VERSION 5.8 ;
BUSBITCHARS "[]" ;
DIVIDERCHAR "/" ;
UNITS
    DATABASE MICRONS 1000 ;
END UNITS

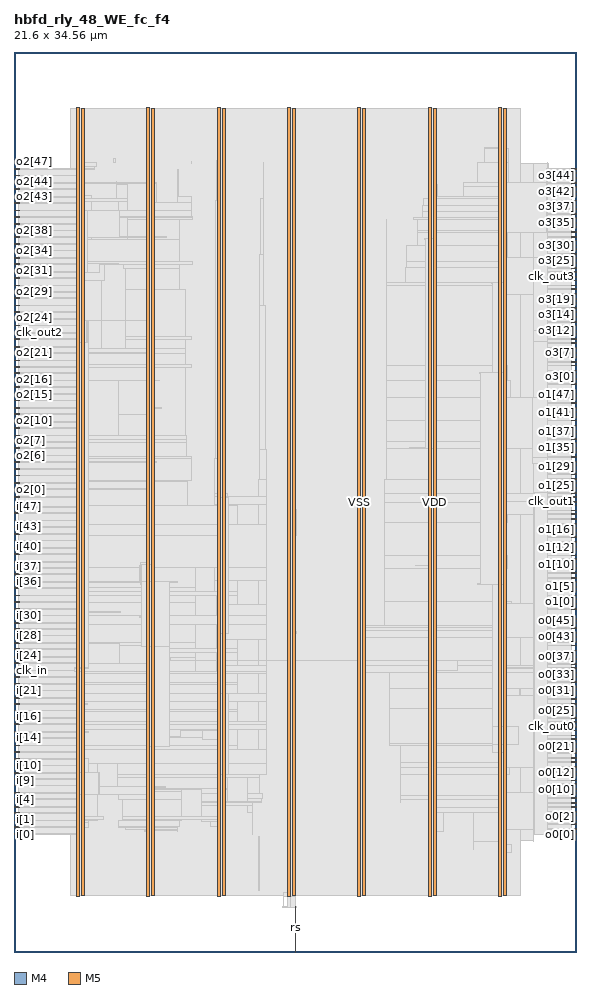
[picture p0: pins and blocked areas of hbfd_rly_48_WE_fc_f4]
MACRO hbfd_rly_48_WE_fc_f4
  FOREIGN hbfd_rly_48_WE_fc_f4 0 0 ;
  CLASS BLOCK ;
  SIZE 21.6 BY 34.56 ;
  PIN clk_in
    DIRECTION INPUT ;
    USE SIGNAL ;
    PORT
      LAYER M4 ;
        RECT  0 10.8 0.192 10.824 ;
    END
  END clk_in
  PIN clk_out0
    DIRECTION OUTPUT ;
    USE SIGNAL ;
    PORT
      LAYER M4 ;
        RECT  21.408 8.64 21.6 8.664 ;
    END
  END clk_out0
  PIN clk_out1
    DIRECTION OUTPUT ;
    USE SIGNAL ;
    PORT
      LAYER M4 ;
        RECT  21.408 17.28 21.6 17.304 ;
    END
  END clk_out1
  PIN clk_out2
    DIRECTION OUTPUT ;
    USE SIGNAL ;
    PORT
      LAYER M4 ;
        RECT  0 23.76 0.192 23.784 ;
    END
  END clk_out2
  PIN clk_out3
    DIRECTION OUTPUT ;
    USE SIGNAL ;
    PORT
      LAYER M4 ;
        RECT  21.408 25.92 21.6 25.944 ;
    END
  END clk_out3
  PIN i[0]
    DIRECTION INPUT ;
    USE SIGNAL ;
    PORT
      LAYER M4 ;
        RECT  0 4.512 0.192 4.536 ;
    END
  END i[0]
  PIN i[10]
    DIRECTION INPUT ;
    USE SIGNAL ;
    PORT
      LAYER M4 ;
        RECT  0 7.152 0.192 7.176 ;
    END
  END i[10]
  PIN i[11]
    DIRECTION INPUT ;
    USE SIGNAL ;
    PORT
      LAYER M4 ;
        RECT  0 7.392 0.192 7.416 ;
    END
  END i[11]
  PIN i[12]
    DIRECTION INPUT ;
    USE SIGNAL ;
    PORT
      LAYER M4 ;
        RECT  0 7.68 0.192 7.704 ;
    END
  END i[12]
  PIN i[13]
    DIRECTION INPUT ;
    USE SIGNAL ;
    PORT
      LAYER M4 ;
        RECT  0 7.92 0.192 7.944 ;
    END
  END i[13]
  PIN i[14]
    DIRECTION INPUT ;
    USE SIGNAL ;
    PORT
      LAYER M4 ;
        RECT  0 8.208 0.192 8.232 ;
    END
  END i[14]
  PIN i[15]
    DIRECTION INPUT ;
    USE SIGNAL ;
    PORT
      LAYER M4 ;
        RECT  0 8.448 0.192 8.472 ;
    END
  END i[15]
  PIN i[16]
    DIRECTION INPUT ;
    USE SIGNAL ;
    PORT
      LAYER M4 ;
        RECT  0 8.736 0.192 8.76 ;
    END
  END i[16]
  PIN i[17]
    DIRECTION INPUT ;
    USE SIGNAL ;
    PORT
      LAYER M4 ;
        RECT  0 8.976 0.192 9 ;
    END
  END i[17]
  PIN i[18]
    DIRECTION INPUT ;
    USE SIGNAL ;
    PORT
      LAYER M4 ;
        RECT  0 9.264 0.192 9.288 ;
    END
  END i[18]
  PIN i[19]
    DIRECTION INPUT ;
    USE SIGNAL ;
    PORT
      LAYER M4 ;
        RECT  0 9.504 0.192 9.528 ;
    END
  END i[19]
  PIN i[1]
    DIRECTION INPUT ;
    USE SIGNAL ;
    PORT
      LAYER M4 ;
        RECT  0 4.8 0.192 4.824 ;
    END
  END i[1]
  PIN i[20]
    DIRECTION INPUT ;
    USE SIGNAL ;
    PORT
      LAYER M4 ;
        RECT  0 9.744 0.192 9.768 ;
    END
  END i[20]
  PIN i[21]
    DIRECTION INPUT ;
    USE SIGNAL ;
    PORT
      LAYER M4 ;
        RECT  0 10.032 0.192 10.056 ;
    END
  END i[21]
  PIN i[22]
    DIRECTION INPUT ;
    USE SIGNAL ;
    PORT
      LAYER M4 ;
        RECT  0 10.272 0.192 10.296 ;
    END
  END i[22]
  PIN i[23]
    DIRECTION INPUT ;
    USE SIGNAL ;
    PORT
      LAYER M4 ;
        RECT  0 10.56 0.192 10.584 ;
    END
  END i[23]
  PIN i[24]
    DIRECTION INPUT ;
    USE SIGNAL ;
    PORT
      LAYER M4 ;
        RECT  0 11.088 0.192 11.112 ;
    END
  END i[24]
  PIN i[25]
    DIRECTION INPUT ;
    USE SIGNAL ;
    PORT
      LAYER M4 ;
        RECT  0 11.328 0.192 11.352 ;
    END
  END i[25]
  PIN i[26]
    DIRECTION INPUT ;
    USE SIGNAL ;
    PORT
      LAYER M4 ;
        RECT  0 11.616 0.192 11.64 ;
    END
  END i[26]
  PIN i[27]
    DIRECTION INPUT ;
    USE SIGNAL ;
    PORT
      LAYER M4 ;
        RECT  0 11.856 0.192 11.88 ;
    END
  END i[27]
  PIN i[28]
    DIRECTION INPUT ;
    USE SIGNAL ;
    PORT
      LAYER M4 ;
        RECT  0 12.144 0.192 12.168 ;
    END
  END i[28]
  PIN i[29]
    DIRECTION INPUT ;
    USE SIGNAL ;
    PORT
      LAYER M4 ;
        RECT  0 12.384 0.192 12.408 ;
    END
  END i[29]
  PIN i[2]
    DIRECTION INPUT ;
    USE SIGNAL ;
    PORT
      LAYER M4 ;
        RECT  0 5.04 0.192 5.064 ;
    END
  END i[2]
  PIN i[30]
    DIRECTION INPUT ;
    USE SIGNAL ;
    PORT
      LAYER M4 ;
        RECT  0 12.624 0.192 12.648 ;
    END
  END i[30]
  PIN i[31]
    DIRECTION INPUT ;
    USE SIGNAL ;
    PORT
      LAYER M4 ;
        RECT  0 12.912 0.192 12.936 ;
    END
  END i[31]
  PIN i[32]
    DIRECTION INPUT ;
    USE SIGNAL ;
    PORT
      LAYER M4 ;
        RECT  0 13.152 0.192 13.176 ;
    END
  END i[32]
  PIN i[33]
    DIRECTION INPUT ;
    USE SIGNAL ;
    PORT
      LAYER M4 ;
        RECT  0 13.44 0.192 13.464 ;
    END
  END i[33]
  PIN i[34]
    DIRECTION INPUT ;
    USE SIGNAL ;
    PORT
      LAYER M4 ;
        RECT  0 13.68 0.192 13.704 ;
    END
  END i[34]
  PIN i[35]
    DIRECTION INPUT ;
    USE SIGNAL ;
    PORT
      LAYER M4 ;
        RECT  0 13.968 0.192 13.992 ;
    END
  END i[35]
  PIN i[36]
    DIRECTION INPUT ;
    USE SIGNAL ;
    PORT
      LAYER M4 ;
        RECT  0 14.208 0.192 14.232 ;
    END
  END i[36]
  PIN i[37]
    DIRECTION INPUT ;
    USE SIGNAL ;
    PORT
      LAYER M4 ;
        RECT  0 14.496 0.192 14.52 ;
    END
  END i[37]
  PIN i[38]
    DIRECTION INPUT ;
    USE SIGNAL ;
    PORT
      LAYER M4 ;
        RECT  0 14.736 0.192 14.76 ;
    END
  END i[38]
  PIN i[39]
    DIRECTION INPUT ;
    USE SIGNAL ;
    PORT
      LAYER M4 ;
        RECT  0 14.976 0.192 15 ;
    END
  END i[39]
  PIN i[3]
    DIRECTION INPUT ;
    USE SIGNAL ;
    PORT
      LAYER M4 ;
        RECT  0 5.328 0.192 5.352 ;
    END
  END i[3]
  PIN i[40]
    DIRECTION INPUT ;
    USE SIGNAL ;
    PORT
      LAYER M4 ;
        RECT  0 15.264 0.192 15.288 ;
    END
  END i[40]
  PIN i[41]
    DIRECTION INPUT ;
    USE SIGNAL ;
    PORT
      LAYER M4 ;
        RECT  0 15.504 0.192 15.528 ;
    END
  END i[41]
  PIN i[42]
    DIRECTION INPUT ;
    USE SIGNAL ;
    PORT
      LAYER M4 ;
        RECT  0 15.792 0.192 15.816 ;
    END
  END i[42]
  PIN i[43]
    DIRECTION INPUT ;
    USE SIGNAL ;
    PORT
      LAYER M4 ;
        RECT  0 16.032 0.192 16.056 ;
    END
  END i[43]
  PIN i[44]
    DIRECTION INPUT ;
    USE SIGNAL ;
    PORT
      LAYER M4 ;
        RECT  0 16.32 0.192 16.344 ;
    END
  END i[44]
  PIN i[45]
    DIRECTION INPUT ;
    USE SIGNAL ;
    PORT
      LAYER M4 ;
        RECT  0 16.56 0.192 16.584 ;
    END
  END i[45]
  PIN i[46]
    DIRECTION INPUT ;
    USE SIGNAL ;
    PORT
      LAYER M4 ;
        RECT  0 16.848 0.192 16.872 ;
    END
  END i[46]
  PIN i[47]
    DIRECTION INPUT ;
    USE SIGNAL ;
    PORT
      LAYER M4 ;
        RECT  0 17.088 0.192 17.112 ;
    END
  END i[47]
  PIN i[4]
    DIRECTION INPUT ;
    USE SIGNAL ;
    PORT
      LAYER M4 ;
        RECT  0 5.568 0.192 5.592 ;
    END
  END i[4]
  PIN i[5]
    DIRECTION INPUT ;
    USE SIGNAL ;
    PORT
      LAYER M4 ;
        RECT  0 5.856 0.192 5.88 ;
    END
  END i[5]
  PIN i[6]
    DIRECTION INPUT ;
    USE SIGNAL ;
    PORT
      LAYER M4 ;
        RECT  0 6.096 0.192 6.12 ;
    END
  END i[6]
  PIN i[7]
    DIRECTION INPUT ;
    USE SIGNAL ;
    PORT
      LAYER M4 ;
        RECT  0 6.384 0.192 6.408 ;
    END
  END i[7]
  PIN i[8]
    DIRECTION INPUT ;
    USE SIGNAL ;
    PORT
      LAYER M4 ;
        RECT  0 6.624 0.192 6.648 ;
    END
  END i[8]
  PIN i[9]
    DIRECTION INPUT ;
    USE SIGNAL ;
    PORT
      LAYER M4 ;
        RECT  0 6.864 0.192 6.888 ;
    END
  END i[9]
  PIN o0[0]
    DIRECTION OUTPUT ;
    USE SIGNAL ;
    PORT
      LAYER M4 ;
        RECT  21.408 4.512 21.6 4.536 ;
    END
  END o0[0]
  PIN o0[10]
    DIRECTION OUTPUT ;
    USE SIGNAL ;
    PORT
      LAYER M4 ;
        RECT  21.408 6.24 21.6 6.264 ;
    END
  END o0[10]
  PIN o0[11]
    DIRECTION OUTPUT ;
    USE SIGNAL ;
    PORT
      LAYER M4 ;
        RECT  21.408 6.432 21.6 6.456 ;
    END
  END o0[11]
  PIN o0[12]
    DIRECTION OUTPUT ;
    USE SIGNAL ;
    PORT
      LAYER M4 ;
        RECT  21.408 6.576 21.6 6.6 ;
    END
  END o0[12]
  PIN o0[13]
    DIRECTION OUTPUT ;
    USE SIGNAL ;
    PORT
      LAYER M4 ;
        RECT  21.408 6.768 21.6 6.792 ;
    END
  END o0[13]
  PIN o0[14]
    DIRECTION OUTPUT ;
    USE SIGNAL ;
    PORT
      LAYER M4 ;
        RECT  21.408 6.912 21.6 6.936 ;
    END
  END o0[14]
  PIN o0[15]
    DIRECTION OUTPUT ;
    USE SIGNAL ;
    PORT
      LAYER M4 ;
        RECT  21.408 7.104 21.6 7.128 ;
    END
  END o0[15]
  PIN o0[16]
    DIRECTION OUTPUT ;
    USE SIGNAL ;
    PORT
      LAYER M4 ;
        RECT  21.408 7.296 21.6 7.32 ;
    END
  END o0[16]
  PIN o0[17]
    DIRECTION OUTPUT ;
    USE SIGNAL ;
    PORT
      LAYER M4 ;
        RECT  21.408 7.44 21.6 7.464 ;
    END
  END o0[17]
  PIN o0[18]
    DIRECTION OUTPUT ;
    USE SIGNAL ;
    PORT
      LAYER M4 ;
        RECT  21.408 7.632 21.6 7.656 ;
    END
  END o0[18]
  PIN o0[19]
    DIRECTION OUTPUT ;
    USE SIGNAL ;
    PORT
      LAYER M4 ;
        RECT  21.408 7.776 21.6 7.8 ;
    END
  END o0[19]
  PIN o0[1]
    DIRECTION OUTPUT ;
    USE SIGNAL ;
    PORT
      LAYER M4 ;
        RECT  21.408 4.704 21.6 4.728 ;
    END
  END o0[1]
  PIN o0[20]
    DIRECTION OUTPUT ;
    USE SIGNAL ;
    PORT
      LAYER M4 ;
        RECT  21.408 7.968 21.6 7.992 ;
    END
  END o0[20]
  PIN o0[21]
    DIRECTION OUTPUT ;
    USE SIGNAL ;
    PORT
      LAYER M4 ;
        RECT  21.408 8.16 21.6 8.184 ;
    END
  END o0[21]
  PIN o0[22]
    DIRECTION OUTPUT ;
    USE SIGNAL ;
    PORT
      LAYER M4 ;
        RECT  21.408 8.304 21.6 8.328 ;
    END
  END o0[22]
  PIN o0[23]
    DIRECTION OUTPUT ;
    USE SIGNAL ;
    PORT
      LAYER M4 ;
        RECT  21.408 8.496 21.6 8.52 ;
    END
  END o0[23]
  PIN o0[24]
    DIRECTION OUTPUT ;
    USE SIGNAL ;
    PORT
      LAYER M4 ;
        RECT  21.408 8.832 21.6 8.856 ;
    END
  END o0[24]
  PIN o0[25]
    DIRECTION OUTPUT ;
    USE SIGNAL ;
    PORT
      LAYER M4 ;
        RECT  21.408 8.976 21.6 9 ;
    END
  END o0[25]
  PIN o0[26]
    DIRECTION OUTPUT ;
    USE SIGNAL ;
    PORT
      LAYER M4 ;
        RECT  21.408 9.168 21.6 9.192 ;
    END
  END o0[26]
  PIN o0[27]
    DIRECTION OUTPUT ;
    USE SIGNAL ;
    PORT
      LAYER M4 ;
        RECT  21.408 9.36 21.6 9.384 ;
    END
  END o0[27]
  PIN o0[28]
    DIRECTION OUTPUT ;
    USE SIGNAL ;
    PORT
      LAYER M4 ;
        RECT  21.408 9.504 21.6 9.528 ;
    END
  END o0[28]
  PIN o0[29]
    DIRECTION OUTPUT ;
    USE SIGNAL ;
    PORT
      LAYER M4 ;
        RECT  21.408 9.696 21.6 9.72 ;
    END
  END o0[29]
  PIN o0[2]
    DIRECTION OUTPUT ;
    USE SIGNAL ;
    PORT
      LAYER M4 ;
        RECT  21.408 4.896 21.6 4.92 ;
    END
  END o0[2]
  PIN o0[30]
    DIRECTION OUTPUT ;
    USE SIGNAL ;
    PORT
      LAYER M4 ;
        RECT  21.408 9.84 21.6 9.864 ;
    END
  END o0[30]
  PIN o0[31]
    DIRECTION OUTPUT ;
    USE SIGNAL ;
    PORT
      LAYER M4 ;
        RECT  21.408 10.032 21.6 10.056 ;
    END
  END o0[31]
  PIN o0[32]
    DIRECTION OUTPUT ;
    USE SIGNAL ;
    PORT
      LAYER M4 ;
        RECT  21.408 10.176 21.6 10.2 ;
    END
  END o0[32]
  PIN o0[33]
    DIRECTION OUTPUT ;
    USE SIGNAL ;
    PORT
      LAYER M4 ;
        RECT  21.408 10.368 21.6 10.392 ;
    END
  END o0[33]
  PIN o0[34]
    DIRECTION OUTPUT ;
    USE SIGNAL ;
    PORT
      LAYER M4 ;
        RECT  21.408 10.56 21.6 10.584 ;
    END
  END o0[34]
  PIN o0[35]
    DIRECTION OUTPUT ;
    USE SIGNAL ;
    PORT
      LAYER M4 ;
        RECT  21.408 10.704 21.6 10.728 ;
    END
  END o0[35]
  PIN o0[36]
    DIRECTION OUTPUT ;
    USE SIGNAL ;
    PORT
      LAYER M4 ;
        RECT  21.408 10.896 21.6 10.92 ;
    END
  END o0[36]
  PIN o0[37]
    DIRECTION OUTPUT ;
    USE SIGNAL ;
    PORT
      LAYER M4 ;
        RECT  21.408 11.04 21.6 11.064 ;
    END
  END o0[37]
  PIN o0[38]
    DIRECTION OUTPUT ;
    USE SIGNAL ;
    PORT
      LAYER M4 ;
        RECT  21.408 11.232 21.6 11.256 ;
    END
  END o0[38]
  PIN o0[39]
    DIRECTION OUTPUT ;
    USE SIGNAL ;
    PORT
      LAYER M4 ;
        RECT  21.408 11.376 21.6 11.4 ;
    END
  END o0[39]
  PIN o0[3]
    DIRECTION OUTPUT ;
    USE SIGNAL ;
    PORT
      LAYER M4 ;
        RECT  21.408 5.04 21.6 5.064 ;
    END
  END o0[3]
  PIN o0[40]
    DIRECTION OUTPUT ;
    USE SIGNAL ;
    PORT
      LAYER M4 ;
        RECT  21.408 11.568 21.6 11.592 ;
    END
  END o0[40]
  PIN o0[41]
    DIRECTION OUTPUT ;
    USE SIGNAL ;
    PORT
      LAYER M4 ;
        RECT  21.408 11.76 21.6 11.784 ;
    END
  END o0[41]
  PIN o0[42]
    DIRECTION OUTPUT ;
    USE SIGNAL ;
    PORT
      LAYER M4 ;
        RECT  21.408 11.904 21.6 11.928 ;
    END
  END o0[42]
  PIN o0[43]
    DIRECTION OUTPUT ;
    USE SIGNAL ;
    PORT
      LAYER M4 ;
        RECT  21.408 12.096 21.6 12.12 ;
    END
  END o0[43]
  PIN o0[44]
    DIRECTION OUTPUT ;
    USE SIGNAL ;
    PORT
      LAYER M4 ;
        RECT  21.408 12.24 21.6 12.264 ;
    END
  END o0[44]
  PIN o0[45]
    DIRECTION OUTPUT ;
    USE SIGNAL ;
    PORT
      LAYER M4 ;
        RECT  21.408 12.432 21.6 12.456 ;
    END
  END o0[45]
  PIN o0[46]
    DIRECTION OUTPUT ;
    USE SIGNAL ;
    PORT
      LAYER M4 ;
        RECT  21.408 12.624 21.6 12.648 ;
    END
  END o0[46]
  PIN o0[47]
    DIRECTION OUTPUT ;
    USE SIGNAL ;
    PORT
      LAYER M4 ;
        RECT  21.408 12.768 21.6 12.792 ;
    END
  END o0[47]
  PIN o0[4]
    DIRECTION OUTPUT ;
    USE SIGNAL ;
    PORT
      LAYER M4 ;
        RECT  21.408 5.232 21.6 5.256 ;
    END
  END o0[4]
  PIN o0[5]
    DIRECTION OUTPUT ;
    USE SIGNAL ;
    PORT
      LAYER M4 ;
        RECT  21.408 5.376 21.6 5.4 ;
    END
  END o0[5]
  PIN o0[6]
    DIRECTION OUTPUT ;
    USE SIGNAL ;
    PORT
      LAYER M4 ;
        RECT  21.408 5.568 21.6 5.592 ;
    END
  END o0[6]
  PIN o0[7]
    DIRECTION OUTPUT ;
    USE SIGNAL ;
    PORT
      LAYER M4 ;
        RECT  21.408 5.712 21.6 5.736 ;
    END
  END o0[7]
  PIN o0[8]
    DIRECTION OUTPUT ;
    USE SIGNAL ;
    PORT
      LAYER M4 ;
        RECT  21.408 5.904 21.6 5.928 ;
    END
  END o0[8]
  PIN o0[9]
    DIRECTION OUTPUT ;
    USE SIGNAL ;
    PORT
      LAYER M4 ;
        RECT  21.408 6.096 21.6 6.12 ;
    END
  END o0[9]
  PIN o1[0]
    DIRECTION OUTPUT ;
    USE SIGNAL ;
    PORT
      LAYER M4 ;
        RECT  21.408 13.152 21.6 13.176 ;
    END
  END o1[0]
  PIN o1[10]
    DIRECTION OUTPUT ;
    USE SIGNAL ;
    PORT
      LAYER M4 ;
        RECT  21.408 14.88 21.6 14.904 ;
    END
  END o1[10]
  PIN o1[11]
    DIRECTION OUTPUT ;
    USE SIGNAL ;
    PORT
      LAYER M4 ;
        RECT  21.408 15.072 21.6 15.096 ;
    END
  END o1[11]
  PIN o1[12]
    DIRECTION OUTPUT ;
    USE SIGNAL ;
    PORT
      LAYER M4 ;
        RECT  21.408 15.216 21.6 15.24 ;
    END
  END o1[12]
  PIN o1[13]
    DIRECTION OUTPUT ;
    USE SIGNAL ;
    PORT
      LAYER M4 ;
        RECT  21.408 15.408 21.6 15.432 ;
    END
  END o1[13]
  PIN o1[14]
    DIRECTION OUTPUT ;
    USE SIGNAL ;
    PORT
      LAYER M4 ;
        RECT  21.408 15.552 21.6 15.576 ;
    END
  END o1[14]
  PIN o1[15]
    DIRECTION OUTPUT ;
    USE SIGNAL ;
    PORT
      LAYER M4 ;
        RECT  21.408 15.744 21.6 15.768 ;
    END
  END o1[15]
  PIN o1[16]
    DIRECTION OUTPUT ;
    USE SIGNAL ;
    PORT
      LAYER M4 ;
        RECT  21.408 15.936 21.6 15.96 ;
    END
  END o1[16]
  PIN o1[17]
    DIRECTION OUTPUT ;
    USE SIGNAL ;
    PORT
      LAYER M4 ;
        RECT  21.408 16.08 21.6 16.104 ;
    END
  END o1[17]
  PIN o1[18]
    DIRECTION OUTPUT ;
    USE SIGNAL ;
    PORT
      LAYER M4 ;
        RECT  21.408 16.272 21.6 16.296 ;
    END
  END o1[18]
  PIN o1[19]
    DIRECTION OUTPUT ;
    USE SIGNAL ;
    PORT
      LAYER M4 ;
        RECT  21.408 16.416 21.6 16.44 ;
    END
  END o1[19]
  PIN o1[1]
    DIRECTION OUTPUT ;
    USE SIGNAL ;
    PORT
      LAYER M4 ;
        RECT  21.408 13.344 21.6 13.368 ;
    END
  END o1[1]
  PIN o1[20]
    DIRECTION OUTPUT ;
    USE SIGNAL ;
    PORT
      LAYER M4 ;
        RECT  21.408 16.608 21.6 16.632 ;
    END
  END o1[20]
  PIN o1[21]
    DIRECTION OUTPUT ;
    USE SIGNAL ;
    PORT
      LAYER M4 ;
        RECT  21.408 16.8 21.6 16.824 ;
    END
  END o1[21]
  PIN o1[22]
    DIRECTION OUTPUT ;
    USE SIGNAL ;
    PORT
      LAYER M4 ;
        RECT  21.408 16.944 21.6 16.968 ;
    END
  END o1[22]
  PIN o1[23]
    DIRECTION OUTPUT ;
    USE SIGNAL ;
    PORT
      LAYER M4 ;
        RECT  21.408 17.136 21.6 17.16 ;
    END
  END o1[23]
  PIN o1[24]
    DIRECTION OUTPUT ;
    USE SIGNAL ;
    PORT
      LAYER M4 ;
        RECT  21.408 17.472 21.6 17.496 ;
    END
  END o1[24]
  PIN o1[25]
    DIRECTION OUTPUT ;
    USE SIGNAL ;
    PORT
      LAYER M4 ;
        RECT  21.408 17.616 21.6 17.64 ;
    END
  END o1[25]
  PIN o1[26]
    DIRECTION OUTPUT ;
    USE SIGNAL ;
    PORT
      LAYER M4 ;
        RECT  21.408 17.808 21.6 17.832 ;
    END
  END o1[26]
  PIN o1[27]
    DIRECTION OUTPUT ;
    USE SIGNAL ;
    PORT
      LAYER M4 ;
        RECT  21.408 18 21.6 18.024 ;
    END
  END o1[27]
  PIN o1[28]
    DIRECTION OUTPUT ;
    USE SIGNAL ;
    PORT
      LAYER M4 ;
        RECT  21.408 18.144 21.6 18.168 ;
    END
  END o1[28]
  PIN o1[29]
    DIRECTION OUTPUT ;
    USE SIGNAL ;
    PORT
      LAYER M4 ;
        RECT  21.408 18.336 21.6 18.36 ;
    END
  END o1[29]
  PIN o1[2]
    DIRECTION OUTPUT ;
    USE SIGNAL ;
    PORT
      LAYER M4 ;
        RECT  21.408 13.536 21.6 13.56 ;
    END
  END o1[2]
  PIN o1[30]
    DIRECTION OUTPUT ;
    USE SIGNAL ;
    PORT
      LAYER M4 ;
        RECT  21.408 18.48 21.6 18.504 ;
    END
  END o1[30]
  PIN o1[31]
    DIRECTION OUTPUT ;
    USE SIGNAL ;
    PORT
      LAYER M4 ;
        RECT  21.408 18.672 21.6 18.696 ;
    END
  END o1[31]
  PIN o1[32]
    DIRECTION OUTPUT ;
    USE SIGNAL ;
    PORT
      LAYER M4 ;
        RECT  21.408 18.816 21.6 18.84 ;
    END
  END o1[32]
  PIN o1[33]
    DIRECTION OUTPUT ;
    USE SIGNAL ;
    PORT
      LAYER M4 ;
        RECT  21.408 19.008 21.6 19.032 ;
    END
  END o1[33]
  PIN o1[34]
    DIRECTION OUTPUT ;
    USE SIGNAL ;
    PORT
      LAYER M4 ;
        RECT  21.408 19.2 21.6 19.224 ;
    END
  END o1[34]
  PIN o1[35]
    DIRECTION OUTPUT ;
    USE SIGNAL ;
    PORT
      LAYER M4 ;
        RECT  21.408 19.344 21.6 19.368 ;
    END
  END o1[35]
  PIN o1[36]
    DIRECTION OUTPUT ;
    USE SIGNAL ;
    PORT
      LAYER M4 ;
        RECT  21.408 19.536 21.6 19.56 ;
    END
  END o1[36]
  PIN o1[37]
    DIRECTION OUTPUT ;
    USE SIGNAL ;
    PORT
      LAYER M4 ;
        RECT  21.408 19.68 21.6 19.704 ;
    END
  END o1[37]
  PIN o1[38]
    DIRECTION OUTPUT ;
    USE SIGNAL ;
    PORT
      LAYER M4 ;
        RECT  21.408 19.872 21.6 19.896 ;
    END
  END o1[38]
  PIN o1[39]
    DIRECTION OUTPUT ;
    USE SIGNAL ;
    PORT
      LAYER M4 ;
        RECT  21.408 20.016 21.6 20.04 ;
    END
  END o1[39]
  PIN o1[3]
    DIRECTION OUTPUT ;
    USE SIGNAL ;
    PORT
      LAYER M4 ;
        RECT  21.408 13.68 21.6 13.704 ;
    END
  END o1[3]
  PIN o1[40]
    DIRECTION OUTPUT ;
    USE SIGNAL ;
    PORT
      LAYER M4 ;
        RECT  21.408 20.208 21.6 20.232 ;
    END
  END o1[40]
  PIN o1[41]
    DIRECTION OUTPUT ;
    USE SIGNAL ;
    PORT
      LAYER M4 ;
        RECT  21.408 20.4 21.6 20.424 ;
    END
  END o1[41]
  PIN o1[42]
    DIRECTION OUTPUT ;
    USE SIGNAL ;
    PORT
      LAYER M4 ;
        RECT  21.408 20.544 21.6 20.568 ;
    END
  END o1[42]
  PIN o1[43]
    DIRECTION OUTPUT ;
    USE SIGNAL ;
    PORT
      LAYER M4 ;
        RECT  21.408 20.736 21.6 20.76 ;
    END
  END o1[43]
  PIN o1[44]
    DIRECTION OUTPUT ;
    USE SIGNAL ;
    PORT
      LAYER M4 ;
        RECT  21.408 20.88 21.6 20.904 ;
    END
  END o1[44]
  PIN o1[45]
    DIRECTION OUTPUT ;
    USE SIGNAL ;
    PORT
      LAYER M4 ;
        RECT  21.408 21.072 21.6 21.096 ;
    END
  END o1[45]
  PIN o1[46]
    DIRECTION OUTPUT ;
    USE SIGNAL ;
    PORT
      LAYER M4 ;
        RECT  21.408 21.264 21.6 21.288 ;
    END
  END o1[46]
  PIN o1[47]
    DIRECTION OUTPUT ;
    USE SIGNAL ;
    PORT
      LAYER M4 ;
        RECT  21.408 21.408 21.6 21.432 ;
    END
  END o1[47]
  PIN o1[4]
    DIRECTION OUTPUT ;
    USE SIGNAL ;
    PORT
      LAYER M4 ;
        RECT  21.408 13.872 21.6 13.896 ;
    END
  END o1[4]
  PIN o1[5]
    DIRECTION OUTPUT ;
    USE SIGNAL ;
    PORT
      LAYER M4 ;
        RECT  21.408 14.016 21.6 14.04 ;
    END
  END o1[5]
  PIN o1[6]
    DIRECTION OUTPUT ;
    USE SIGNAL ;
    PORT
      LAYER M4 ;
        RECT  21.408 14.208 21.6 14.232 ;
    END
  END o1[6]
  PIN o1[7]
    DIRECTION OUTPUT ;
    USE SIGNAL ;
    PORT
      LAYER M4 ;
        RECT  21.408 14.352 21.6 14.376 ;
    END
  END o1[7]
  PIN o1[8]
    DIRECTION OUTPUT ;
    USE SIGNAL ;
    PORT
      LAYER M4 ;
        RECT  21.408 14.544 21.6 14.568 ;
    END
  END o1[8]
  PIN o1[9]
    DIRECTION OUTPUT ;
    USE SIGNAL ;
    PORT
      LAYER M4 ;
        RECT  21.408 14.736 21.6 14.76 ;
    END
  END o1[9]
  PIN o2[0]
    DIRECTION OUTPUT ;
    USE SIGNAL ;
    PORT
      LAYER M4 ;
        RECT  0 17.472 0.192 17.496 ;
    END
  END o2[0]
  PIN o2[10]
    DIRECTION OUTPUT ;
    USE SIGNAL ;
    PORT
      LAYER M4 ;
        RECT  0 20.112 0.192 20.136 ;
    END
  END o2[10]
  PIN o2[11]
    DIRECTION OUTPUT ;
    USE SIGNAL ;
    PORT
      LAYER M4 ;
        RECT  0 20.352 0.192 20.376 ;
    END
  END o2[11]
  PIN o2[12]
    DIRECTION OUTPUT ;
    USE SIGNAL ;
    PORT
      LAYER M4 ;
        RECT  0 20.64 0.192 20.664 ;
    END
  END o2[12]
  PIN o2[13]
    DIRECTION OUTPUT ;
    USE SIGNAL ;
    PORT
      LAYER M4 ;
        RECT  0 20.88 0.192 20.904 ;
    END
  END o2[13]
  PIN o2[14]
    DIRECTION OUTPUT ;
    USE SIGNAL ;
    PORT
      LAYER M4 ;
        RECT  0 21.168 0.192 21.192 ;
    END
  END o2[14]
  PIN o2[15]
    DIRECTION OUTPUT ;
    USE SIGNAL ;
    PORT
      LAYER M4 ;
        RECT  0 21.408 0.192 21.432 ;
    END
  END o2[15]
  PIN o2[16]
    DIRECTION OUTPUT ;
    USE SIGNAL ;
    PORT
      LAYER M4 ;
        RECT  0 21.696 0.192 21.72 ;
    END
  END o2[16]
  PIN o2[17]
    DIRECTION OUTPUT ;
    USE SIGNAL ;
    PORT
      LAYER M4 ;
        RECT  0 21.936 0.192 21.96 ;
    END
  END o2[17]
  PIN o2[18]
    DIRECTION OUTPUT ;
    USE SIGNAL ;
    PORT
      LAYER M4 ;
        RECT  0 22.224 0.192 22.248 ;
    END
  END o2[18]
  PIN o2[19]
    DIRECTION OUTPUT ;
    USE SIGNAL ;
    PORT
      LAYER M4 ;
        RECT  0 22.464 0.192 22.488 ;
    END
  END o2[19]
  PIN o2[1]
    DIRECTION OUTPUT ;
    USE SIGNAL ;
    PORT
      LAYER M4 ;
        RECT  0 17.76 0.192 17.784 ;
    END
  END o2[1]
  PIN o2[20]
    DIRECTION OUTPUT ;
    USE SIGNAL ;
    PORT
      LAYER M4 ;
        RECT  0 22.704 0.192 22.728 ;
    END
  END o2[20]
  PIN o2[21]
    DIRECTION OUTPUT ;
    USE SIGNAL ;
    PORT
      LAYER M4 ;
        RECT  0 22.992 0.192 23.016 ;
    END
  END o2[21]
  PIN o2[22]
    DIRECTION OUTPUT ;
    USE SIGNAL ;
    PORT
      LAYER M4 ;
        RECT  0 23.232 0.192 23.256 ;
    END
  END o2[22]
  PIN o2[23]
    DIRECTION OUTPUT ;
    USE SIGNAL ;
    PORT
      LAYER M4 ;
        RECT  0 23.52 0.192 23.544 ;
    END
  END o2[23]
  PIN o2[24]
    DIRECTION OUTPUT ;
    USE SIGNAL ;
    PORT
      LAYER M4 ;
        RECT  0 24.048 0.192 24.072 ;
    END
  END o2[24]
  PIN o2[25]
    DIRECTION OUTPUT ;
    USE SIGNAL ;
    PORT
      LAYER M4 ;
        RECT  0 24.288 0.192 24.312 ;
    END
  END o2[25]
  PIN o2[26]
    DIRECTION OUTPUT ;
    USE SIGNAL ;
    PORT
      LAYER M4 ;
        RECT  0 24.576 0.192 24.6 ;
    END
  END o2[26]
  PIN o2[27]
    DIRECTION OUTPUT ;
    USE SIGNAL ;
    PORT
      LAYER M4 ;
        RECT  0 24.816 0.192 24.84 ;
    END
  END o2[27]
  PIN o2[28]
    DIRECTION OUTPUT ;
    USE SIGNAL ;
    PORT
      LAYER M4 ;
        RECT  0 25.104 0.192 25.128 ;
    END
  END o2[28]
  PIN o2[29]
    DIRECTION OUTPUT ;
    USE SIGNAL ;
    PORT
      LAYER M4 ;
        RECT  0 25.344 0.192 25.368 ;
    END
  END o2[29]
  PIN o2[2]
    DIRECTION OUTPUT ;
    USE SIGNAL ;
    PORT
      LAYER M4 ;
        RECT  0 18 0.192 18.024 ;
    END
  END o2[2]
  PIN o2[30]
    DIRECTION OUTPUT ;
    USE SIGNAL ;
    PORT
      LAYER M4 ;
        RECT  0 25.584 0.192 25.608 ;
    END
  END o2[30]
  PIN o2[31]
    DIRECTION OUTPUT ;
    USE SIGNAL ;
    PORT
      LAYER M4 ;
        RECT  0 25.872 0.192 25.896 ;
    END
  END o2[31]
  PIN o2[32]
    DIRECTION OUTPUT ;
    USE SIGNAL ;
    PORT
      LAYER M4 ;
        RECT  0 26.112 0.192 26.136 ;
    END
  END o2[32]
  PIN o2[33]
    DIRECTION OUTPUT ;
    USE SIGNAL ;
    PORT
      LAYER M4 ;
        RECT  0 26.4 0.192 26.424 ;
    END
  END o2[33]
  PIN o2[34]
    DIRECTION OUTPUT ;
    USE SIGNAL ;
    PORT
      LAYER M4 ;
        RECT  0 26.64 0.192 26.664 ;
    END
  END o2[34]
  PIN o2[35]
    DIRECTION OUTPUT ;
    USE SIGNAL ;
    PORT
      LAYER M4 ;
        RECT  0 26.928 0.192 26.952 ;
    END
  END o2[35]
  PIN o2[36]
    DIRECTION OUTPUT ;
    USE SIGNAL ;
    PORT
      LAYER M4 ;
        RECT  0 27.168 0.192 27.192 ;
    END
  END o2[36]
  PIN o2[37]
    DIRECTION OUTPUT ;
    USE SIGNAL ;
    PORT
      LAYER M4 ;
        RECT  0 27.456 0.192 27.48 ;
    END
  END o2[37]
  PIN o2[38]
    DIRECTION OUTPUT ;
    USE SIGNAL ;
    PORT
      LAYER M4 ;
        RECT  0 27.696 0.192 27.72 ;
    END
  END o2[38]
  PIN o2[39]
    DIRECTION OUTPUT ;
    USE SIGNAL ;
    PORT
      LAYER M4 ;
        RECT  0 27.936 0.192 27.96 ;
    END
  END o2[39]
  PIN o2[3]
    DIRECTION OUTPUT ;
    USE SIGNAL ;
    PORT
      LAYER M4 ;
        RECT  0 18.288 0.192 18.312 ;
    END
  END o2[3]
  PIN o2[40]
    DIRECTION OUTPUT ;
    USE SIGNAL ;
    PORT
      LAYER M4 ;
        RECT  0 28.224 0.192 28.248 ;
    END
  END o2[40]
  PIN o2[41]
    DIRECTION OUTPUT ;
    USE SIGNAL ;
    PORT
      LAYER M4 ;
        RECT  0 28.464 0.192 28.488 ;
    END
  END o2[41]
  PIN o2[42]
    DIRECTION OUTPUT ;
    USE SIGNAL ;
    PORT
      LAYER M4 ;
        RECT  0 28.752 0.192 28.776 ;
    END
  END o2[42]
  PIN o2[43]
    DIRECTION OUTPUT ;
    USE SIGNAL ;
    PORT
      LAYER M4 ;
        RECT  0 28.992 0.192 29.016 ;
    END
  END o2[43]
  PIN o2[44]
    DIRECTION OUTPUT ;
    USE SIGNAL ;
    PORT
      LAYER M4 ;
        RECT  0 29.28 0.192 29.304 ;
    END
  END o2[44]
  PIN o2[45]
    DIRECTION OUTPUT ;
    USE SIGNAL ;
    PORT
      LAYER M4 ;
        RECT  0 29.52 0.192 29.544 ;
    END
  END o2[45]
  PIN o2[46]
    DIRECTION OUTPUT ;
    USE SIGNAL ;
    PORT
      LAYER M4 ;
        RECT  0 29.808 0.192 29.832 ;
    END
  END o2[46]
  PIN o2[47]
    DIRECTION OUTPUT ;
    USE SIGNAL ;
    PORT
      LAYER M4 ;
        RECT  0 30.048 0.192 30.072 ;
    END
  END o2[47]
  PIN o2[4]
    DIRECTION OUTPUT ;
    USE SIGNAL ;
    PORT
      LAYER M4 ;
        RECT  0 18.528 0.192 18.552 ;
    END
  END o2[4]
  PIN o2[5]
    DIRECTION OUTPUT ;
    USE SIGNAL ;
    PORT
      LAYER M4 ;
        RECT  0 18.816 0.192 18.84 ;
    END
  END o2[5]
  PIN o2[6]
    DIRECTION OUTPUT ;
    USE SIGNAL ;
    PORT
      LAYER M4 ;
        RECT  0 19.056 0.192 19.08 ;
    END
  END o2[6]
  PIN o2[7]
    DIRECTION OUTPUT ;
    USE SIGNAL ;
    PORT
      LAYER M4 ;
        RECT  0 19.344 0.192 19.368 ;
    END
  END o2[7]
  PIN o2[8]
    DIRECTION OUTPUT ;
    USE SIGNAL ;
    PORT
      LAYER M4 ;
        RECT  0 19.584 0.192 19.608 ;
    END
  END o2[8]
  PIN o2[9]
    DIRECTION OUTPUT ;
    USE SIGNAL ;
    PORT
      LAYER M4 ;
        RECT  0 19.824 0.192 19.848 ;
    END
  END o2[9]
  PIN o3[0]
    DIRECTION OUTPUT ;
    USE SIGNAL ;
    PORT
      LAYER M4 ;
        RECT  21.408 21.792 21.6 21.816 ;
    END
  END o3[0]
  PIN o3[10]
    DIRECTION OUTPUT ;
    USE SIGNAL ;
    PORT
      LAYER M4 ;
        RECT  21.408 23.52 21.6 23.544 ;
    END
  END o3[10]
  PIN o3[11]
    DIRECTION OUTPUT ;
    USE SIGNAL ;
    PORT
      LAYER M4 ;
        RECT  21.408 23.712 21.6 23.736 ;
    END
  END o3[11]
  PIN o3[12]
    DIRECTION OUTPUT ;
    USE SIGNAL ;
    PORT
      LAYER M4 ;
        RECT  21.408 23.856 21.6 23.88 ;
    END
  END o3[12]
  PIN o3[13]
    DIRECTION OUTPUT ;
    USE SIGNAL ;
    PORT
      LAYER M4 ;
        RECT  21.408 24.048 21.6 24.072 ;
    END
  END o3[13]
  PIN o3[14]
    DIRECTION OUTPUT ;
    USE SIGNAL ;
    PORT
      LAYER M4 ;
        RECT  21.408 24.192 21.6 24.216 ;
    END
  END o3[14]
  PIN o3[15]
    DIRECTION OUTPUT ;
    USE SIGNAL ;
    PORT
      LAYER M4 ;
        RECT  21.408 24.384 21.6 24.408 ;
    END
  END o3[15]
  PIN o3[16]
    DIRECTION OUTPUT ;
    USE SIGNAL ;
    PORT
      LAYER M4 ;
        RECT  21.408 24.576 21.6 24.6 ;
    END
  END o3[16]
  PIN o3[17]
    DIRECTION OUTPUT ;
    USE SIGNAL ;
    PORT
      LAYER M4 ;
        RECT  21.408 24.72 21.6 24.744 ;
    END
  END o3[17]
  PIN o3[18]
    DIRECTION OUTPUT ;
    USE SIGNAL ;
    PORT
      LAYER M4 ;
        RECT  21.408 24.912 21.6 24.936 ;
    END
  END o3[18]
  PIN o3[19]
    DIRECTION OUTPUT ;
    USE SIGNAL ;
    PORT
      LAYER M4 ;
        RECT  21.408 25.056 21.6 25.08 ;
    END
  END o3[19]
  PIN o3[1]
    DIRECTION OUTPUT ;
    USE SIGNAL ;
    PORT
      LAYER M4 ;
        RECT  21.408 21.984 21.6 22.008 ;
    END
  END o3[1]
  PIN o3[20]
    DIRECTION OUTPUT ;
    USE SIGNAL ;
    PORT
      LAYER M4 ;
        RECT  21.408 25.248 21.6 25.272 ;
    END
  END o3[20]
  PIN o3[21]
    DIRECTION OUTPUT ;
    USE SIGNAL ;
    PORT
      LAYER M4 ;
        RECT  21.408 25.44 21.6 25.464 ;
    END
  END o3[21]
  PIN o3[22]
    DIRECTION OUTPUT ;
    USE SIGNAL ;
    PORT
      LAYER M4 ;
        RECT  21.408 25.584 21.6 25.608 ;
    END
  END o3[22]
  PIN o3[23]
    DIRECTION OUTPUT ;
    USE SIGNAL ;
    PORT
      LAYER M4 ;
        RECT  21.408 25.776 21.6 25.8 ;
    END
  END o3[23]
  PIN o3[24]
    DIRECTION OUTPUT ;
    USE SIGNAL ;
    PORT
      LAYER M4 ;
        RECT  21.408 26.112 21.6 26.136 ;
    END
  END o3[24]
  PIN o3[25]
    DIRECTION OUTPUT ;
    USE SIGNAL ;
    PORT
      LAYER M4 ;
        RECT  21.408 26.256 21.6 26.28 ;
    END
  END o3[25]
  PIN o3[26]
    DIRECTION OUTPUT ;
    USE SIGNAL ;
    PORT
      LAYER M4 ;
        RECT  21.408 26.448 21.6 26.472 ;
    END
  END o3[26]
  PIN o3[27]
    DIRECTION OUTPUT ;
    USE SIGNAL ;
    PORT
      LAYER M4 ;
        RECT  21.408 26.64 21.6 26.664 ;
    END
  END o3[27]
  PIN o3[28]
    DIRECTION OUTPUT ;
    USE SIGNAL ;
    PORT
      LAYER M4 ;
        RECT  21.408 26.784 21.6 26.808 ;
    END
  END o3[28]
  PIN o3[29]
    DIRECTION OUTPUT ;
    USE SIGNAL ;
    PORT
      LAYER M4 ;
        RECT  21.408 26.976 21.6 27 ;
    END
  END o3[29]
  PIN o3[2]
    DIRECTION OUTPUT ;
    USE SIGNAL ;
    PORT
      LAYER M4 ;
        RECT  21.408 22.176 21.6 22.2 ;
    END
  END o3[2]
  PIN o3[30]
    DIRECTION OUTPUT ;
    USE SIGNAL ;
    PORT
      LAYER M4 ;
        RECT  21.408 27.12 21.6 27.144 ;
    END
  END o3[30]
  PIN o3[31]
    DIRECTION OUTPUT ;
    USE SIGNAL ;
    PORT
      LAYER M4 ;
        RECT  21.408 27.312 21.6 27.336 ;
    END
  END o3[31]
  PIN o3[32]
    DIRECTION OUTPUT ;
    USE SIGNAL ;
    PORT
      LAYER M4 ;
        RECT  21.408 27.456 21.6 27.48 ;
    END
  END o3[32]
  PIN o3[33]
    DIRECTION OUTPUT ;
    USE SIGNAL ;
    PORT
      LAYER M4 ;
        RECT  21.408 27.648 21.6 27.672 ;
    END
  END o3[33]
  PIN o3[34]
    DIRECTION OUTPUT ;
    USE SIGNAL ;
    PORT
      LAYER M4 ;
        RECT  21.408 27.84 21.6 27.864 ;
    END
  END o3[34]
  PIN o3[35]
    DIRECTION OUTPUT ;
    USE SIGNAL ;
    PORT
      LAYER M4 ;
        RECT  21.408 27.984 21.6 28.008 ;
    END
  END o3[35]
  PIN o3[36]
    DIRECTION OUTPUT ;
    USE SIGNAL ;
    PORT
      LAYER M4 ;
        RECT  21.408 28.176 21.6 28.2 ;
    END
  END o3[36]
  PIN o3[37]
    DIRECTION OUTPUT ;
    USE SIGNAL ;
    PORT
      LAYER M4 ;
        RECT  21.408 28.32 21.6 28.344 ;
    END
  END o3[37]
  PIN o3[38]
    DIRECTION OUTPUT ;
    USE SIGNAL ;
    PORT
      LAYER M4 ;
        RECT  21.408 28.512 21.6 28.536 ;
    END
  END o3[38]
  PIN o3[39]
    DIRECTION OUTPUT ;
    USE SIGNAL ;
    PORT
      LAYER M4 ;
        RECT  21.408 28.656 21.6 28.68 ;
    END
  END o3[39]
  PIN o3[3]
    DIRECTION OUTPUT ;
    USE SIGNAL ;
    PORT
      LAYER M4 ;
        RECT  21.408 22.32 21.6 22.344 ;
    END
  END o3[3]
  PIN o3[40]
    DIRECTION OUTPUT ;
    USE SIGNAL ;
    PORT
      LAYER M4 ;
        RECT  21.408 28.848 21.6 28.872 ;
    END
  END o3[40]
  PIN o3[41]
    DIRECTION OUTPUT ;
    USE SIGNAL ;
    PORT
      LAYER M4 ;
        RECT  21.408 29.04 21.6 29.064 ;
    END
  END o3[41]
  PIN o3[42]
    DIRECTION OUTPUT ;
    USE SIGNAL ;
    PORT
      LAYER M4 ;
        RECT  21.408 29.184 21.6 29.208 ;
    END
  END o3[42]
  PIN o3[43]
    DIRECTION OUTPUT ;
    USE SIGNAL ;
    PORT
      LAYER M4 ;
        RECT  21.408 29.376 21.6 29.4 ;
    END
  END o3[43]
  PIN o3[44]
    DIRECTION OUTPUT ;
    USE SIGNAL ;
    PORT
      LAYER M4 ;
        RECT  21.408 29.52 21.6 29.544 ;
    END
  END o3[44]
  PIN o3[45]
    DIRECTION OUTPUT ;
    USE SIGNAL ;
    PORT
      LAYER M4 ;
        RECT  21.408 29.712 21.6 29.736 ;
    END
  END o3[45]
  PIN o3[46]
    DIRECTION OUTPUT ;
    USE SIGNAL ;
    PORT
      LAYER M4 ;
        RECT  21.408 29.904 21.6 29.928 ;
    END
  END o3[46]
  PIN o3[47]
    DIRECTION OUTPUT ;
    USE SIGNAL ;
    PORT
      LAYER M4 ;
        RECT  21.408 30.048 21.6 30.072 ;
    END
  END o3[47]
  PIN o3[4]
    DIRECTION OUTPUT ;
    USE SIGNAL ;
    PORT
      LAYER M4 ;
        RECT  21.408 22.512 21.6 22.536 ;
    END
  END o3[4]
  PIN o3[5]
    DIRECTION OUTPUT ;
    USE SIGNAL ;
    PORT
      LAYER M4 ;
        RECT  21.408 22.656 21.6 22.68 ;
    END
  END o3[5]
  PIN o3[6]
    DIRECTION OUTPUT ;
    USE SIGNAL ;
    PORT
      LAYER M4 ;
        RECT  21.408 22.848 21.6 22.872 ;
    END
  END o3[6]
  PIN o3[7]
    DIRECTION OUTPUT ;
    USE SIGNAL ;
    PORT
      LAYER M4 ;
        RECT  21.408 22.992 21.6 23.016 ;
    END
  END o3[7]
  PIN o3[8]
    DIRECTION OUTPUT ;
    USE SIGNAL ;
    PORT
      LAYER M4 ;
        RECT  21.408 23.184 21.6 23.208 ;
    END
  END o3[8]
  PIN o3[9]
    DIRECTION OUTPUT ;
    USE SIGNAL ;
    PORT
      LAYER M4 ;
        RECT  21.408 23.376 21.6 23.4 ;
    END
  END o3[9]
  PIN rs
    DIRECTION INPUT ;
    USE SIGNAL ;
    PORT
      LAYER M5 ;
        RECT  10.8 0 10.824 0.192 ;
    END
    PORT
      LAYER M5 ;
        RECT  10.8 0.144 10.824 1.763 ;
    END
  END rs
  PIN VDD
    DIRECTION INOUT ;
    USE POWER ;
    PORT
      LAYER M5 ;
        RECT  18.792 2.151 18.912 32.409 ;
        RECT  16.092 2.151 16.212 32.409 ;
        RECT  13.392 2.151 13.512 32.409 ;
        RECT  10.692 2.151 10.812 32.409 ;
        RECT  7.992 2.151 8.112 32.409 ;
        RECT  5.292 2.151 5.412 32.409 ;
        RECT  2.592 2.151 2.712 32.409 ;
    END
  END VDD
  PIN VSS
    DIRECTION INOUT ;
    USE GROUND ;
    PORT
      LAYER M5 ;
        RECT  18.6 2.137 18.72 32.423 ;
        RECT  15.9 2.137 16.02 32.423 ;
        RECT  13.2 2.137 13.32 32.423 ;
        RECT  10.5 2.137 10.62 32.423 ;
        RECT  7.8 2.137 7.92 32.423 ;
        RECT  5.1 2.137 5.22 32.423 ;
        RECT  2.4 2.137 2.52 32.423 ;
    END
  END VSS
  # OT_OBS_CLOSED layer=M5 d_um=1.536 added=0
  OBS
    LAYER RVTN ;
     RECT  2.16 2.16 19.44 2.295 ;
     RECT  2.16 2.565 19.44 2.835 ;
     RECT  2.16 3.105 19.44 3.375 ;
     RECT  2.16 3.645 19.44 3.915 ;
     RECT  2.16 4.185 19.44 4.455 ;
     RECT  2.16 4.725 19.44 4.995 ;
     RECT  2.16 5.265 19.44 5.535 ;
     RECT  2.16 5.805 19.44 6.075 ;
     RECT  2.16 6.345 19.44 6.615 ;
     RECT  2.16 6.885 19.44 7.155 ;
     RECT  2.16 7.425 19.44 7.695 ;
     RECT  2.16 7.965 19.44 8.235 ;
     RECT  2.16 8.505 19.44 8.775 ;
     RECT  2.16 9.045 19.44 9.315 ;
     RECT  2.16 9.585 19.44 9.855 ;
     RECT  2.16 10.125 19.44 10.395 ;
     RECT  2.16 10.665 19.44 10.935 ;
     RECT  2.16 11.205 19.44 11.475 ;
     RECT  2.16 11.745 19.44 12.015 ;
     RECT  2.16 12.285 19.44 12.555 ;
     RECT  2.16 12.825 19.44 13.095 ;
     RECT  2.16 13.365 19.44 13.635 ;
     RECT  2.16 13.905 19.44 14.175 ;
     RECT  2.16 14.445 19.44 14.715 ;
     RECT  2.16 14.985 19.44 15.255 ;
     RECT  2.16 15.525 19.44 15.795 ;
     RECT  2.16 16.065 19.44 16.335 ;
     RECT  2.16 16.605 19.44 16.875 ;
     RECT  2.16 17.145 19.44 17.415 ;
     RECT  2.16 17.685 19.44 17.955 ;
     RECT  2.16 18.225 19.44 18.495 ;
     RECT  2.16 18.765 19.44 19.035 ;
     RECT  2.16 19.305 19.44 19.575 ;
     RECT  2.16 19.845 19.44 20.115 ;
     RECT  2.16 20.385 19.44 20.655 ;
     RECT  2.16 20.925 19.44 21.195 ;
     RECT  2.16 21.465 19.44 21.735 ;
     RECT  2.16 22.005 19.44 22.275 ;
     RECT  2.16 22.545 19.44 22.815 ;
     RECT  2.16 23.085 19.44 23.355 ;
     RECT  2.16 23.625 19.44 23.895 ;
     RECT  2.16 24.165 19.44 24.435 ;
     RECT  2.16 24.705 19.44 24.975 ;
     RECT  2.16 25.245 19.44 25.515 ;
     RECT  2.16 25.785 19.44 26.055 ;
     RECT  2.16 26.325 19.44 26.595 ;
     RECT  2.16 26.865 19.44 27.135 ;
     RECT  2.16 27.405 19.44 27.675 ;
     RECT  2.16 27.945 19.44 28.215 ;
     RECT  2.16 28.485 19.44 28.755 ;
     RECT  2.16 29.025 19.44 29.295 ;
     RECT  2.16 29.565 19.44 29.835 ;
     RECT  2.16 30.105 19.44 30.375 ;
     RECT  2.16 30.645 19.44 30.915 ;
     RECT  2.16 31.185 19.44 31.455 ;
     RECT  2.16 31.725 19.44 31.995 ;
     RECT  2.16 32.265 19.44 32.4 ;
    LAYER RVTP ;
     RECT  2.16 2.295 19.44 2.565 ;
     RECT  2.16 2.835 19.44 3.105 ;
     RECT  2.16 3.375 19.44 3.645 ;
     RECT  2.16 3.915 19.44 4.185 ;
     RECT  2.16 4.455 19.44 4.725 ;
     RECT  2.16 4.995 19.44 5.265 ;
     RECT  2.16 5.535 19.44 5.805 ;
     RECT  2.16 6.075 19.44 6.345 ;
     RECT  2.16 6.615 19.44 6.885 ;
     RECT  2.16 7.155 19.44 7.425 ;
     RECT  2.16 7.695 19.44 7.965 ;
     RECT  2.16 8.235 19.44 8.505 ;
     RECT  2.16 8.775 19.44 9.045 ;
     RECT  2.16 9.315 19.44 9.585 ;
     RECT  2.16 9.855 19.44 10.125 ;
     RECT  2.16 10.395 19.44 10.665 ;
     RECT  2.16 10.935 19.44 11.205 ;
     RECT  2.16 11.475 19.44 11.745 ;
     RECT  2.16 12.015 19.44 12.285 ;
     RECT  2.16 12.555 19.44 12.825 ;
     RECT  2.16 13.095 19.44 13.365 ;
     RECT  2.16 13.635 19.44 13.905 ;
     RECT  2.16 14.175 19.44 14.445 ;
     RECT  2.16 14.715 19.44 14.985 ;
     RECT  2.16 15.255 19.44 15.525 ;
     RECT  2.16 15.795 19.44 16.065 ;
     RECT  2.16 16.335 19.44 16.605 ;
     RECT  2.16 16.875 19.44 17.145 ;
     RECT  2.16 17.415 19.44 17.685 ;
     RECT  2.16 17.955 19.44 18.225 ;
     RECT  2.16 18.495 19.44 18.765 ;
     RECT  2.16 19.035 19.44 19.305 ;
     RECT  2.16 19.575 19.44 19.845 ;
     RECT  2.16 20.115 19.44 20.385 ;
     RECT  2.16 20.655 19.44 20.925 ;
     RECT  2.16 21.195 19.44 21.465 ;
     RECT  2.16 21.735 19.44 22.005 ;
     RECT  2.16 22.275 19.44 22.545 ;
     RECT  2.16 22.815 19.44 23.085 ;
     RECT  2.16 23.355 19.44 23.625 ;
     RECT  2.16 23.895 19.44 24.165 ;
     RECT  2.16 24.435 19.44 24.705 ;
     RECT  2.16 24.975 19.44 25.245 ;
     RECT  2.16 25.515 19.44 25.785 ;
     RECT  2.16 26.055 19.44 26.325 ;
     RECT  2.16 26.595 19.44 26.865 ;
     RECT  2.16 27.135 19.44 27.405 ;
     RECT  2.16 27.675 19.44 27.945 ;
     RECT  2.16 28.215 19.44 28.485 ;
     RECT  2.16 28.755 19.44 29.025 ;
     RECT  2.16 29.295 19.44 29.565 ;
     RECT  2.16 29.835 19.44 30.105 ;
     RECT  2.16 30.375 19.44 30.645 ;
     RECT  2.16 30.915 19.44 31.185 ;
     RECT  2.16 31.455 19.44 31.725 ;
     RECT  2.16 31.995 19.44 32.265 ;
    LAYER M1 ;
     RECT  2.16 2.151 19.44 32.409 ;
    LAYER M2 ;
     RECT  0.247 22.716 0.535 22.734 ;
     RECT  0.211 25.416 0.535 25.434 ;
     RECT  0.211 6.822 2.16 6.84 ;
     RECT  0.211 7.74 2.16 7.758 ;
     RECT  0.535 17.046 2.16 17.064 ;
     RECT  0.211 18.126 2.16 18.144 ;
     RECT  0.535 21.636 2.16 22.734 ;
     RECT  0.211 24.066 2.16 24.084 ;
     RECT  0.535 25.056 2.16 25.434 ;
     RECT  2.16 2.151 19.44 32.409 ;
     RECT  19.44 4.266 19.967 30.294 ;
     RECT  19.967 4.536 20.507 24.93 ;
     RECT  19.967 25.794 20.507 30.294 ;
     RECT  20.507 4.536 20.543 8.532 ;
     RECT  20.507 9.936 20.543 11.574 ;
     RECT  20.507 12.456 20.543 13.086 ;
     RECT  20.507 14.148 20.543 16.938 ;
     RECT  20.507 18.036 20.543 24.93 ;
     RECT  20.507 26.028 20.543 29.052 ;
     RECT  20.543 5.076 20.579 5.094 ;
     RECT  20.543 7.326 20.579 7.956 ;
     RECT  20.543 14.184 20.579 14.742 ;
     RECT  20.543 20.394 20.579 20.412 ;
     RECT  20.543 21.438 20.579 22.806 ;
     RECT  20.543 26.766 20.579 26.784 ;
     RECT  20.579 7.326 20.615 7.344 ;
     RECT  20.579 14.184 20.615 14.202 ;
     RECT  20.579 22.788 20.615 22.806 ;
     RECT  20.543 23.868 20.615 23.886 ;
    LAYER M3 ;
     RECT  10.332 1.723 10.35 2.143 ;
     RECT  10.332 2.143 10.605 2.291 ;
     RECT  2.415 2.143 2.505 2.413 ;
     RECT  5.115 2.143 5.205 2.413 ;
     RECT  7.815 2.143 7.905 2.413 ;
     RECT  10.515 2.291 10.605 2.413 ;
     RECT  13.215 2.143 13.305 2.413 ;
     RECT  15.915 2.143 16.005 2.413 ;
     RECT  18.615 2.143 18.705 2.413 ;
     RECT  18.615 2.413 18.897 3.811 ;
     RECT  18.615 3.811 19.098 4.145 ;
     RECT  17.64 3.955 17.658 4.261 ;
     RECT  18.615 4.145 18.897 4.261 ;
     RECT  9.396 2.371 9.414 4.451 ;
     RECT  2.415 2.413 2.697 4.507 ;
     RECT  19.944 4.261 19.962 4.531 ;
     RECT  5.115 2.413 5.397 4.621 ;
     RECT  15.915 2.413 16.197 4.621 ;
     RECT  5.004 4.621 5.397 4.657 ;
     RECT  6.264 4.621 6.282 4.657 ;
     RECT  5.004 4.657 6.282 4.693 ;
     RECT  2.304 4.507 2.697 4.765 ;
     RECT  4.284 4.693 6.282 4.765 ;
     RECT  2.304 4.765 2.862 4.795 ;
     RECT  4.032 4.765 6.282 4.801 ;
     RECT  7.815 2.413 8.097 4.801 ;
     RECT  2.268 4.795 2.862 4.955 ;
     RECT  7.56 4.801 8.097 4.999 ;
     RECT  2.304 4.955 2.862 5.035 ;
     RECT  4.032 4.801 6.354 5.035 ;
     RECT  4.032 5.035 6.426 5.063 ;
     RECT  19.944 4.531 20.538 5.068 ;
     RECT  2.304 5.035 3.222 5.071 ;
     RECT  4.176 5.063 6.426 5.071 ;
     RECT  7.2 4.999 8.097 5.071 ;
     RECT  2.304 5.071 3.438 5.189 ;
     RECT  4.176 5.071 8.097 5.189 ;
     RECT  19.944 5.068 20.574 5.261 ;
     RECT  9.144 4.531 9.162 5.341 ;
     RECT  15.915 4.621 16.506 5.341 ;
     RECT  17.64 4.261 18.897 5.341 ;
     RECT  15.915 5.341 18.897 5.563 ;
     RECT  19.944 5.261 20.538 5.563 ;
     RECT  7.2 5.189 8.097 5.611 ;
     RECT  8.964 5.341 9.162 5.611 ;
     RECT  7.2 5.611 9.162 5.737 ;
     RECT  7.2 5.737 9.486 5.765 ;
     RECT  4.176 5.189 6.426 5.845 ;
     RECT  14.832 5.737 14.85 5.845 ;
     RECT  15.915 5.563 20.538 5.845 ;
     RECT  8.964 5.765 9.486 5.881 ;
     RECT  14.832 5.845 20.538 5.999 ;
     RECT  8.964 5.881 9.558 6.071 ;
     RECT  2.304 5.189 3.222 6.151 ;
     RECT  4.032 5.845 6.426 6.151 ;
     RECT  7.2 5.765 8.19 6.235 ;
     RECT  2.304 6.151 6.426 6.241 ;
     RECT  7.164 6.235 8.19 6.241 ;
     RECT  2.304 6.241 8.19 6.269 ;
     RECT  19.944 5.999 20.538 6.269 ;
     RECT  3.96 6.269 8.19 6.691 ;
     RECT  8.964 6.071 9.414 6.691 ;
     RECT  20.484 6.269 20.538 6.797 ;
     RECT  3.96 6.691 9.414 6.817 ;
     RECT  14.832 5.999 18.897 6.817 ;
     RECT  0.216 6.817 0.234 6.893 ;
     RECT  14.832 6.817 19.026 7.099 ;
     RECT  2.304 6.269 3.222 7.231 ;
     RECT  3.96 6.817 9.702 7.231 ;
     RECT  14.832 7.099 19.422 7.259 ;
     RECT  20.52 6.797 20.538 7.321 ;
     RECT  20.52 7.321 20.61 7.661 ;
     RECT  2.304 7.231 9.702 7.763 ;
     RECT  2.304 7.763 8.586 7.925 ;
     RECT  14.832 7.259 19.314 7.933 ;
     RECT  14.4 7.933 19.314 7.997 ;
     RECT  20.52 7.661 20.574 8.189 ;
     RECT  0.216 7.735 0.234 8.237 ;
     RECT  20.52 8.189 20.538 8.299 ;
     RECT  19.944 8.299 20.538 8.525 ;
     RECT  20.484 8.525 20.538 8.537 ;
     RECT  2.34 7.925 8.586 8.545 ;
     RECT  9.396 7.763 9.702 8.545 ;
     RECT  2.34 8.545 9.702 8.731 ;
     RECT  2.304 8.731 9.702 8.843 ;
     RECT  2.304 8.843 8.586 9.247 ;
     RECT  2.268 9.247 8.586 9.293 ;
     RECT  14.4 7.997 18.954 9.355 ;
     RECT  20.484 8.537 20.502 9.499 ;
     RECT  2.304 9.293 8.586 9.625 ;
     RECT  9.396 8.843 9.702 9.625 ;
     RECT  0.216 9.739 0.234 9.917 ;
     RECT  2.304 9.625 9.702 9.923 ;
     RECT  14.4 9.355 19.422 10.129 ;
     RECT  20.484 9.499 20.538 10.129 ;
     RECT  2.304 9.923 8.586 10.267 ;
     RECT  2.268 10.267 8.586 10.355 ;
     RECT  2.304 10.355 8.586 10.705 ;
     RECT  9.396 9.923 9.702 10.705 ;
     RECT  13.215 2.413 13.497 10.741 ;
     RECT  14.4 10.129 20.538 10.741 ;
     RECT  2.304 10.705 9.702 10.769 ;
     RECT  7.776 10.769 9.702 11.003 ;
     RECT  13.215 10.741 20.538 11.003 ;
     RECT  19.944 11.003 20.538 11.069 ;
     RECT  2.304 10.769 6.966 11.323 ;
     RECT  2.232 11.323 6.966 11.507 ;
     RECT  2.268 11.507 6.966 11.515 ;
     RECT  7.776 11.003 8.586 11.515 ;
     RECT  20.484 11.069 20.538 11.579 ;
     RECT  2.268 11.515 8.586 11.669 ;
     RECT  20.484 11.579 20.502 11.821 ;
     RECT  2.268 11.669 6.966 11.885 ;
     RECT  19.944 11.821 20.502 11.933 ;
     RECT  20.484 11.933 20.502 11.939 ;
     RECT  7.776 11.669 8.586 11.983 ;
     RECT  9.396 11.003 9.702 11.983 ;
     RECT  13.215 11.003 18.897 12.091 ;
     RECT  10.515 2.413 10.797 12.217 ;
     RECT  10.515 12.217 10.854 12.317 ;
     RECT  13.215 12.091 18.99 12.361 ;
     RECT  13.215 12.361 19.422 12.461 ;
     RECT  13.215 12.461 19.098 12.551 ;
     RECT  2.304 11.885 6.966 12.595 ;
     RECT  7.776 11.983 9.702 12.595 ;
     RECT  20.52 12.451 20.538 12.757 ;
     RECT  2.304 12.595 9.702 12.929 ;
     RECT  0.216 12.907 0.234 13.085 ;
     RECT  20.484 12.757 20.538 13.181 ;
     RECT  7.776 12.929 9.702 13.325 ;
     RECT  2.304 12.929 6.966 13.435 ;
     RECT  20.484 13.181 20.502 13.441 ;
     RECT  14.22 12.551 19.098 13.469 ;
     RECT  2.268 13.435 6.966 13.675 ;
     RECT  7.776 13.325 8.586 13.675 ;
     RECT  2.268 13.675 8.586 13.829 ;
     RECT  2.268 13.829 6.966 14.009 ;
     RECT  19.944 13.441 20.502 14.011 ;
     RECT  19.944 14.011 20.538 14.179 ;
     RECT  7.704 13.829 8.586 14.251 ;
     RECT  9.396 13.325 9.702 14.251 ;
     RECT  19.944 14.179 20.61 14.381 ;
     RECT  19.944 14.381 20.574 14.573 ;
     RECT  14.22 13.469 18.897 14.719 ;
     RECT  2.304 14.009 6.966 14.755 ;
     RECT  7.704 14.251 9.702 14.755 ;
     RECT  20.484 14.573 20.574 14.765 ;
     RECT  14.22 14.719 18.954 15.215 ;
     RECT  20.484 14.765 20.538 15.403 ;
     RECT  10.515 12.317 10.797 15.997 ;
     RECT  2.304 14.755 9.702 16.403 ;
     RECT  14.22 15.215 18.897 16.501 ;
     RECT  19.944 15.403 20.538 16.943 ;
     RECT  10.515 15.997 10.854 16.979 ;
     RECT  2.304 16.403 8.586 17.141 ;
     RECT  7.704 17.141 8.586 17.185 ;
     RECT  9.396 16.403 9.702 17.185 ;
     RECT  14.22 16.501 18.954 17.275 ;
     RECT  19.944 16.943 20.502 17.275 ;
     RECT  7.704 17.185 9.702 17.483 ;
     RECT  0.54 17.041 0.558 17.501 ;
     RECT  7.704 17.483 8.19 17.609 ;
     RECT  14.22 17.275 20.502 17.609 ;
     RECT  19.98 17.609 20.502 17.645 ;
     RECT  20.484 17.645 20.502 17.995 ;
     RECT  2.304 17.141 6.678 18.059 ;
     RECT  2.415 18.059 6.678 18.121 ;
     RECT  9.396 17.483 9.702 18.149 ;
     RECT  14.22 17.609 18.897 18.149 ;
     RECT  0.216 18.121 0.234 18.317 ;
     RECT  20.484 17.995 20.538 18.769 ;
     RECT  7.704 17.609 8.097 18.959 ;
     RECT  2.415 18.121 6.822 18.967 ;
     RECT  2.412 18.967 6.822 19.031 ;
     RECT  9.432 18.149 9.702 19.301 ;
     RECT  14.292 18.149 18.897 19.339 ;
     RECT  19.908 18.769 20.538 19.339 ;
     RECT  2.412 19.031 6.606 19.579 ;
     RECT  14.292 19.339 20.538 19.607 ;
     RECT  2.304 19.579 6.606 19.679 ;
     RECT  2.415 19.679 6.606 19.841 ;
     RECT  19.944 19.607 20.538 20.237 ;
     RECT  20.52 20.237 20.538 20.389 ;
     RECT  14.292 19.607 18.99 20.395 ;
     RECT  20.52 20.389 20.574 21.067 ;
     RECT  14.292 20.395 19.422 21.293 ;
     RECT  14.292 21.293 19.062 21.929 ;
     RECT  0.54 21.631 0.558 22.253 ;
     RECT  2.415 19.841 6.57 22.441 ;
     RECT  14.292 21.929 18.954 22.505 ;
     RECT  2.415 22.441 6.822 22.541 ;
     RECT  0.252 22.699 0.27 22.739 ;
     RECT  20.484 21.067 20.574 22.783 ;
     RECT  2.415 22.541 6.57 22.981 ;
     RECT  20.484 22.783 20.61 23.021 ;
     RECT  2.304 22.981 6.57 23.189 ;
     RECT  20.484 23.021 20.538 23.431 ;
     RECT  4.284 23.189 6.57 23.521 ;
     RECT  4.284 23.521 6.822 23.621 ;
     RECT  19.944 23.431 20.538 23.863 ;
     RECT  0.216 23.755 0.234 24.089 ;
     RECT  19.944 23.863 20.61 24.605 ;
     RECT  9.432 19.301 9.666 24.809 ;
     RECT  19.944 24.605 20.538 25.085 ;
     RECT  0.54 25.051 0.558 25.133 ;
     RECT  0.216 25.339 0.234 25.439 ;
     RECT  4.284 23.621 6.57 25.439 ;
     RECT  19.944 25.085 20.502 25.469 ;
     RECT  14.292 22.505 18.897 25.579 ;
     RECT  14.292 25.579 19.422 25.709 ;
     RECT  2.304 23.189 3.366 25.789 ;
     RECT  20.484 25.469 20.502 25.817 ;
     RECT  4.284 25.439 6.354 26.257 ;
     RECT  15.048 25.709 19.422 26.285 ;
     RECT  2.304 25.789 3.474 26.395 ;
     RECT  4.212 26.257 6.354 26.395 ;
     RECT  2.304 26.395 6.354 26.401 ;
     RECT  2.304 26.401 6.858 26.519 ;
     RECT  15.084 26.285 19.422 26.519 ;
     RECT  20.52 26.023 20.538 26.761 ;
     RECT  9.432 24.809 9.594 26.789 ;
     RECT  20.52 26.761 20.574 26.971 ;
     RECT  15.084 26.519 18.954 27.131 ;
     RECT  20.484 26.971 20.574 27.149 ;
     RECT  2.304 26.519 6.354 27.365 ;
     RECT  15.48 27.131 18.954 27.643 ;
     RECT  15.48 27.643 19.422 27.707 ;
     RECT  4.356 27.365 6.354 28.111 ;
     RECT  15.48 27.707 19.098 28.111 ;
     RECT  14.292 25.709 14.31 28.139 ;
     RECT  15.336 28.111 19.098 28.211 ;
     RECT  4.356 28.111 6.858 28.219 ;
     RECT  4.032 28.219 6.858 28.247 ;
     RECT  15.696 28.211 19.098 28.453 ;
     RECT  4.032 28.247 6.822 28.481 ;
     RECT  15.696 28.453 19.422 28.679 ;
     RECT  5.115 28.481 6.822 28.787 ;
     RECT  2.304 27.365 2.97 28.831 ;
     RECT  4.032 28.481 4.374 28.831 ;
     RECT  7.74 18.959 8.097 28.859 ;
     RECT  2.304 28.831 4.374 28.949 ;
     RECT  9.468 26.789 9.594 28.949 ;
     RECT  15.732 28.679 19.422 28.949 ;
     RECT  6.264 28.787 6.822 29.021 ;
     RECT  15.915 28.949 19.422 29.021 ;
     RECT  2.304 28.949 2.97 29.057 ;
     RECT  20.484 27.149 20.538 29.213 ;
     RECT  17.244 29.021 19.422 29.408 ;
     RECT  2.304 29.057 2.697 29.489 ;
     RECT  3.924 28.949 4.374 29.489 ;
     RECT  15.915 29.021 16.254 29.489 ;
     RECT  5.115 28.787 5.454 29.549 ;
     RECT  17.244 29.408 18.99 29.561 ;
     RECT  3.924 29.489 3.942 29.597 ;
     RECT  6.264 29.021 6.318 30.029 ;
     RECT  2.412 29.489 2.697 30.037 ;
     RECT  20.484 29.213 20.502 30.037 ;
     RECT  2.412 30.037 3.078 30.077 ;
     RECT  20.448 30.037 20.502 30.077 ;
     RECT  2.415 30.077 3.078 30.145 ;
     RECT  2.415 30.145 3.186 30.299 ;
     RECT  9.576 28.949 9.594 30.299 ;
     RECT  17.784 29.561 18.99 30.299 ;
     RECT  20.484 30.077 20.502 30.299 ;
     RECT  6.804 30.271 6.822 30.371 ;
     RECT  7.776 28.859 8.097 30.407 ;
     RECT  3.816 30.307 3.906 30.479 ;
     RECT  18.072 30.299 18.99 30.839 ;
     RECT  18.072 30.839 18.897 30.911 ;
     RECT  2.415 30.299 2.697 32.147 ;
     RECT  5.115 29.549 5.397 32.147 ;
     RECT  7.815 30.407 8.097 32.147 ;
     RECT  10.515 16.979 10.797 32.147 ;
     RECT  13.215 12.551 13.497 32.147 ;
     RECT  15.915 29.489 16.197 32.147 ;
     RECT  18.615 30.911 18.897 32.147 ;
     RECT  2.415 32.147 2.505 32.417 ;
     RECT  5.115 32.147 5.205 32.417 ;
     RECT  7.815 32.147 7.905 32.417 ;
     RECT  10.515 32.147 10.605 32.417 ;
     RECT  13.215 32.147 13.305 32.417 ;
     RECT  15.915 32.147 16.005 32.417 ;
     RECT  18.615 32.147 18.705 32.417 ;
    LAYER M4 ;
     RECT  0.192 4.512 2.408 4.536 ;
     RECT  0.156 4.536 2.408 4.8 ;
     RECT  0.192 4.8 2.408 4.824 ;
     RECT  0.156 4.824 2.408 5.04 ;
     RECT  0.192 5.04 2.408 5.064 ;
     RECT  0.156 5.064 2.408 5.328 ;
     RECT  0.192 5.328 2.408 5.352 ;
     RECT  0.156 5.352 2.408 5.568 ;
     RECT  0.192 5.568 2.408 5.592 ;
     RECT  0.156 5.592 2.408 5.856 ;
     RECT  0.192 5.856 2.408 5.88 ;
     RECT  0.156 5.88 2.408 6.096 ;
     RECT  0.192 6.096 2.408 6.12 ;
     RECT  0.156 6.12 2.408 6.384 ;
     RECT  0.192 6.384 2.408 6.408 ;
     RECT  0.156 6.408 2.408 6.624 ;
     RECT  0.192 6.624 2.408 6.648 ;
     RECT  0.156 6.648 2.408 6.864 ;
     RECT  0.192 6.864 2.408 6.888 ;
     RECT  0.156 6.888 2.408 7.152 ;
     RECT  0.192 7.152 2.408 7.176 ;
     RECT  0.156 7.176 2.408 7.392 ;
     RECT  0.192 7.392 2.408 7.416 ;
     RECT  0.156 7.416 2.408 7.68 ;
     RECT  0.192 7.68 2.408 7.704 ;
     RECT  0.156 7.704 2.408 7.92 ;
     RECT  0.192 7.92 2.408 7.944 ;
     RECT  0.156 7.944 2.408 8.208 ;
     RECT  0.192 8.208 2.408 8.232 ;
     RECT  0.156 8.232 2.408 8.448 ;
     RECT  0.192 8.448 2.408 8.472 ;
     RECT  0.156 8.472 2.408 8.736 ;
     RECT  0.192 8.736 2.408 8.76 ;
     RECT  0.156 8.76 2.408 8.976 ;
     RECT  0.192 8.976 2.408 9 ;
     RECT  0.156 9 2.408 9.264 ;
     RECT  0.192 9.264 2.408 9.288 ;
     RECT  0.156 9.288 2.408 9.504 ;
     RECT  0.192 9.504 2.408 9.528 ;
     RECT  0.156 9.528 2.408 9.744 ;
     RECT  0.192 9.744 2.408 9.768 ;
     RECT  0.156 9.768 2.408 10.032 ;
     RECT  0.192 10.032 2.408 10.056 ;
     RECT  0.156 10.056 2.408 10.272 ;
     RECT  0.192 10.272 2.408 10.296 ;
     RECT  0.156 10.296 2.408 10.56 ;
     RECT  0.192 10.56 2.408 10.584 ;
     RECT  0.156 10.584 2.408 10.8 ;
     RECT  0.192 10.8 2.408 10.824 ;
     RECT  0.156 10.824 2.408 11.088 ;
     RECT  0.192 11.088 2.408 11.112 ;
     RECT  0.156 11.112 2.408 11.328 ;
     RECT  0.192 11.328 2.408 11.352 ;
     RECT  0.156 11.352 2.408 11.616 ;
     RECT  0.192 11.616 2.408 11.64 ;
     RECT  0.156 11.64 2.408 11.856 ;
     RECT  0.192 11.856 2.408 11.88 ;
     RECT  0.156 11.88 2.408 12.144 ;
     RECT  0.192 12.144 2.408 12.168 ;
     RECT  0.156 12.168 2.408 12.384 ;
     RECT  0.192 12.384 2.408 12.408 ;
     RECT  0.156 12.408 2.408 12.624 ;
     RECT  0.192 12.624 2.408 12.648 ;
     RECT  0.156 12.648 2.408 12.912 ;
     RECT  0.192 12.912 2.408 12.936 ;
     RECT  0.156 12.936 2.408 13.152 ;
     RECT  0.192 13.152 2.408 13.176 ;
     RECT  0.156 13.176 2.408 13.44 ;
     RECT  0.192 13.44 2.408 13.464 ;
     RECT  0.156 13.464 2.408 13.68 ;
     RECT  0.192 13.68 2.408 13.704 ;
     RECT  0.156 13.704 2.408 13.968 ;
     RECT  0.192 13.968 2.408 13.992 ;
     RECT  0.156 13.992 2.408 14.208 ;
     RECT  0.192 14.208 2.408 14.232 ;
     RECT  0.156 14.232 2.408 14.496 ;
     RECT  0.192 14.496 2.408 14.52 ;
     RECT  0.156 14.52 2.408 14.736 ;
     RECT  0.192 14.736 2.408 14.76 ;
     RECT  0.156 14.76 2.408 14.976 ;
     RECT  0.192 14.976 2.408 15 ;
     RECT  0.156 15 2.408 15.264 ;
     RECT  0.192 15.264 2.408 15.288 ;
     RECT  0.156 15.288 2.408 15.504 ;
     RECT  0.192 15.504 2.408 15.528 ;
     RECT  0.156 15.528 2.408 15.792 ;
     RECT  0.192 15.792 2.408 15.816 ;
     RECT  0.156 15.816 2.408 16.032 ;
     RECT  0.192 16.032 2.408 16.056 ;
     RECT  0.156 16.056 2.408 16.32 ;
     RECT  0.192 16.32 2.408 16.344 ;
     RECT  0.156 16.344 2.408 16.56 ;
     RECT  0.192 16.56 2.408 16.584 ;
     RECT  0.156 16.584 2.408 16.848 ;
     RECT  0.192 16.848 2.408 16.872 ;
     RECT  0.156 16.872 2.408 17.088 ;
     RECT  0.192 17.088 2.408 17.112 ;
     RECT  0.156 17.112 2.408 17.472 ;
     RECT  0.192 17.472 2.408 17.496 ;
     RECT  0.156 17.496 2.408 17.76 ;
     RECT  0.192 17.76 2.408 17.784 ;
     RECT  0.156 17.784 2.408 18 ;
     RECT  0.192 18 2.408 18.024 ;
     RECT  0.156 18.024 2.408 18.288 ;
     RECT  0.192 18.288 2.408 18.312 ;
     RECT  0.156 18.312 2.408 18.528 ;
     RECT  0.192 18.528 2.408 18.552 ;
     RECT  0.156 18.552 2.408 18.816 ;
     RECT  0.192 18.816 2.408 18.84 ;
     RECT  0.156 18.84 2.408 19.056 ;
     RECT  0.192 19.056 2.408 19.08 ;
     RECT  0.156 19.08 2.408 19.344 ;
     RECT  0.192 19.344 2.408 19.368 ;
     RECT  0.156 19.368 2.408 19.584 ;
     RECT  0.192 19.584 2.408 19.608 ;
     RECT  0.156 19.608 2.408 19.824 ;
     RECT  0.192 19.824 2.408 19.848 ;
     RECT  0.156 19.848 2.408 20.112 ;
     RECT  0.192 20.112 2.408 20.136 ;
     RECT  0.156 20.136 2.408 20.352 ;
     RECT  0.192 20.352 2.408 20.376 ;
     RECT  0.156 20.376 2.408 20.64 ;
     RECT  0.192 20.64 2.408 20.664 ;
     RECT  0.156 20.664 2.408 20.88 ;
     RECT  0.192 20.88 2.408 20.904 ;
     RECT  0.156 20.904 2.408 21.168 ;
     RECT  0.192 21.168 2.408 21.192 ;
     RECT  0.156 21.192 2.408 21.408 ;
     RECT  0.192 21.408 2.408 21.432 ;
     RECT  0.156 21.432 2.408 21.696 ;
     RECT  0.192 21.696 2.408 21.72 ;
     RECT  0.156 21.72 2.408 21.936 ;
     RECT  0.192 21.936 2.408 21.96 ;
     RECT  0.156 21.96 2.408 22.224 ;
     RECT  0.192 22.224 2.408 22.248 ;
     RECT  0.156 22.248 2.408 22.464 ;
     RECT  0.192 22.464 2.408 22.488 ;
     RECT  0.156 22.488 2.408 22.704 ;
     RECT  0.192 22.704 2.408 22.728 ;
     RECT  0.156 22.728 2.408 22.992 ;
     RECT  0.192 22.992 2.408 23.016 ;
     RECT  0.156 23.016 2.408 23.232 ;
     RECT  0.192 23.232 2.408 23.256 ;
     RECT  0.156 23.256 2.408 23.52 ;
     RECT  0.192 23.52 2.408 23.544 ;
     RECT  0.156 23.544 2.408 23.76 ;
     RECT  0.192 23.76 2.408 23.784 ;
     RECT  0.156 23.784 2.408 24.048 ;
     RECT  0.192 24.048 2.408 24.072 ;
     RECT  0.156 24.072 2.408 24.288 ;
     RECT  0.192 24.288 2.408 24.312 ;
     RECT  0.156 24.312 2.408 24.576 ;
     RECT  0.192 24.576 2.408 24.6 ;
     RECT  0.156 24.6 2.408 24.816 ;
     RECT  0.192 24.816 2.408 24.84 ;
     RECT  0.156 24.84 2.408 25.104 ;
     RECT  0.192 25.104 2.408 25.128 ;
     RECT  0.156 25.128 2.408 25.344 ;
     RECT  0.192 25.344 2.408 25.368 ;
     RECT  0.156 25.368 2.408 25.584 ;
     RECT  0.192 25.584 2.408 25.608 ;
     RECT  0.156 25.608 2.408 25.872 ;
     RECT  0.192 25.872 2.408 25.896 ;
     RECT  0.156 25.896 2.408 26.112 ;
     RECT  0.192 26.112 2.408 26.136 ;
     RECT  0.156 26.136 2.408 26.4 ;
     RECT  0.192 26.4 2.408 26.424 ;
     RECT  0.156 26.424 2.408 26.64 ;
     RECT  0.192 26.64 2.408 26.664 ;
     RECT  0.156 26.664 2.408 26.928 ;
     RECT  0.192 26.928 2.408 26.952 ;
     RECT  0.156 26.952 2.408 27.168 ;
     RECT  0.192 27.168 2.408 27.192 ;
     RECT  0.156 27.192 2.408 27.456 ;
     RECT  0.192 27.456 2.408 27.48 ;
     RECT  0.156 27.48 2.408 27.696 ;
     RECT  0.192 27.696 2.408 27.72 ;
     RECT  0.156 27.72 2.408 27.936 ;
     RECT  0.192 27.936 2.408 27.96 ;
     RECT  0.156 27.96 2.408 28.224 ;
     RECT  0.192 28.224 2.408 28.248 ;
     RECT  0.156 28.248 2.408 28.464 ;
     RECT  0.192 28.464 2.408 28.488 ;
     RECT  0.156 28.488 2.408 28.752 ;
     RECT  0.192 28.752 2.408 28.776 ;
     RECT  0.156 28.776 2.408 28.992 ;
     RECT  0.192 28.992 2.408 29.016 ;
     RECT  0.156 29.016 2.408 29.28 ;
     RECT  0.192 29.28 2.408 29.304 ;
     RECT  0.156 29.304 2.408 29.52 ;
     RECT  0.192 29.52 2.408 29.544 ;
     RECT  0.156 29.544 2.408 29.808 ;
     RECT  0.192 29.808 2.408 29.832 ;
     RECT  0.156 29.832 2.408 30.048 ;
     RECT  0.192 30.048 2.408 30.072 ;
     RECT  2.408 2.148 2.512 32.412 ;
     RECT  2.512 2.418 2.704 32.142 ;
     RECT  2.704 15.984 2.801 24.264 ;
     RECT  2.704 9.504 2.837 9.528 ;
     RECT  2.801 17.76 2.837 24.264 ;
     RECT  2.704 26.112 2.837 28.488 ;
     RECT  2.704 10.896 2.867 11.832 ;
     RECT  2.704 6.048 2.873 7.416 ;
     RECT  2.704 8.448 2.873 8.472 ;
     RECT  2.837 22.992 2.873 24.264 ;
     RECT  2.837 26.112 3.269 26.424 ;
     RECT  2.873 6.048 3.277 6.888 ;
     RECT  2.837 19.824 4.025 21.96 ;
     RECT  3.269 26.4 4.025 26.424 ;
     RECT  2.867 11.088 4.061 11.832 ;
     RECT  2.837 27.456 4.061 28.488 ;
     RECT  2.704 13.056 4.097 13.08 ;
     RECT  2.704 14.208 4.813 14.232 ;
     RECT  4.813 14.208 4.844 14.856 ;
     RECT  4.844 14.112 4.849 14.856 ;
     RECT  3.277 6.048 5.108 6.36 ;
     RECT  4.705 7.92 5.108 7.944 ;
     RECT  4.061 11.088 5.108 11.784 ;
     RECT  4.813 12.864 5.108 12.888 ;
     RECT  4.849 14.112 5.108 14.952 ;
     RECT  2.801 15.984 5.108 16.008 ;
     RECT  2.837 17.76 5.108 17.784 ;
     RECT  2.837 18.816 5.108 18.84 ;
     RECT  4.025 20.64 5.108 21.96 ;
     RECT  2.873 22.992 5.108 23.016 ;
     RECT  2.873 24.24 5.108 24.264 ;
     RECT  4.061 27.456 5.108 27.48 ;
     RECT  4.061 28.464 5.108 28.488 ;
     RECT  2.704 29.52 5.108 29.544 ;
     RECT  5.108 2.148 5.212 32.412 ;
     RECT  5.212 2.418 5.404 32.142 ;
     RECT  5.404 18.816 5.465 18.84 ;
     RECT  5.404 29.52 5.465 29.544 ;
     RECT  5.404 21.936 5.573 21.96 ;
     RECT  5.404 20.88 5.645 20.904 ;
     RECT  5.404 6.336 5.825 6.36 ;
     RECT  5.404 27.456 5.861 27.48 ;
     RECT  5.404 28.464 5.969 28.488 ;
     RECT  5.404 7.92 5.987 8.28 ;
     RECT  5.404 11.184 6.028 11.304 ;
     RECT  5.404 14.208 6.293 14.232 ;
     RECT  5.987 8.256 6.397 8.28 ;
     RECT  7.153 6.24 7.189 6.264 ;
     RECT  6.397 8.256 7.225 8.52 ;
     RECT  7.189 6.096 7.808 6.264 ;
     RECT  7.225 8.16 7.808 8.52 ;
     RECT  6.028 11.184 7.808 11.208 ;
     RECT  6.397 13.68 7.808 13.704 ;
     RECT  5.404 15.984 7.808 16.008 ;
     RECT  7.808 2.148 7.912 32.412 ;
     RECT  7.912 2.418 8.104 32.142 ;
     RECT  8.104 6.816 8.243 8.808 ;
     RECT  8.104 9.888 8.243 9.912 ;
     RECT  8.104 12.24 8.243 12.264 ;
     RECT  8.104 13.344 8.243 16.392 ;
     RECT  8.104 17.424 8.243 17.448 ;
     RECT  8.243 6.816 8.245 6.84 ;
     RECT  10.321 1.728 10.508 1.752 ;
     RECT  8.104 11.184 10.508 11.208 ;
     RECT  10.508 1.728 10.612 32.412 ;
     RECT  10.612 1.728 10.804 32.142 ;
     RECT  10.804 1.728 10.835 1.752 ;
     RECT  10.804 11.184 13.208 11.208 ;
     RECT  13.208 2.148 13.312 32.412 ;
     RECT  13.312 2.418 13.504 32.142 ;
     RECT  13.504 11.184 15.908 11.208 ;
     RECT  15.433 14.832 15.908 14.856 ;
     RECT  15.181 19.344 15.908 19.368 ;
     RECT  15.749 27.36 15.908 27.384 ;
     RECT  15.908 2.148 16.012 32.412 ;
     RECT  16.012 2.418 16.204 32.142 ;
     RECT  16.204 10.8 17.021 11.208 ;
     RECT  18.373 7.68 18.608 7.704 ;
     RECT  17.021 11.184 18.608 11.208 ;
     RECT  18.529 12.24 18.608 12.264 ;
     RECT  17.809 14.112 18.608 14.136 ;
     RECT  18.373 17.616 18.608 17.64 ;
     RECT  17.893 22.224 18.608 22.248 ;
     RECT  18.341 25.68 18.608 25.704 ;
     RECT  18.608 2.148 18.712 32.412 ;
     RECT  18.712 2.418 18.904 32.142 ;
     RECT  18.904 19.344 19.897 21.288 ;
     RECT  18.904 4.704 19.933 6.12 ;
     RECT  18.904 7.104 19.933 9.864 ;
     RECT  18.904 10.896 19.933 10.92 ;
     RECT  18.904 12.096 19.933 13.368 ;
     RECT  18.904 16.8 19.933 17.304 ;
     RECT  18.904 25.248 19.933 26.664 ;
     RECT  19.933 4.512 19.969 17.496 ;
     RECT  18.904 27.648 20.437 29.544 ;
     RECT  19.969 4.512 20.473 17.64 ;
     RECT  19.897 19.008 20.473 21.288 ;
     RECT  19.933 23.856 20.473 26.664 ;
     RECT  20.437 27.648 20.473 30.072 ;
     RECT  20.473 4.512 21.408 4.536 ;
     RECT  20.473 4.536 21.42 4.704 ;
     RECT  20.473 4.704 21.408 4.728 ;
     RECT  20.473 4.728 21.42 4.896 ;
     RECT  20.473 4.896 21.408 4.92 ;
     RECT  20.473 4.92 21.42 5.04 ;
     RECT  20.473 5.04 21.408 5.064 ;
     RECT  20.473 5.064 21.42 5.232 ;
     RECT  20.473 5.232 21.408 5.256 ;
     RECT  20.473 5.256 21.42 5.376 ;
     RECT  20.473 5.376 21.408 5.4 ;
     RECT  20.473 5.4 21.42 5.568 ;
     RECT  20.473 5.568 21.408 5.592 ;
     RECT  20.473 5.592 21.42 5.712 ;
     RECT  20.473 5.712 21.408 5.736 ;
     RECT  20.473 5.736 21.42 5.904 ;
     RECT  20.473 5.904 21.408 5.928 ;
     RECT  20.473 5.928 21.42 6.096 ;
     RECT  20.473 6.096 21.408 6.12 ;
     RECT  20.473 6.12 21.42 6.24 ;
     RECT  20.473 6.24 21.408 6.264 ;
     RECT  20.473 6.264 21.42 6.432 ;
     RECT  20.473 6.432 21.408 6.456 ;
     RECT  20.473 6.456 21.42 6.576 ;
     RECT  20.473 6.576 21.408 6.6 ;
     RECT  20.473 6.6 21.42 6.768 ;
     RECT  20.473 6.768 21.408 6.792 ;
     RECT  20.473 6.792 21.42 6.912 ;
     RECT  20.473 6.912 21.408 6.936 ;
     RECT  20.473 6.936 21.42 7.104 ;
     RECT  20.473 7.104 21.408 7.128 ;
     RECT  20.473 7.128 21.42 7.296 ;
     RECT  20.473 7.296 21.408 7.32 ;
     RECT  20.473 7.32 21.42 7.44 ;
     RECT  20.473 7.44 21.408 7.464 ;
     RECT  20.473 7.464 21.42 7.632 ;
     RECT  20.473 7.632 21.408 7.656 ;
     RECT  20.473 7.656 21.42 7.776 ;
     RECT  20.473 7.776 21.408 7.8 ;
     RECT  20.473 7.8 21.42 7.968 ;
     RECT  20.473 7.968 21.408 7.992 ;
     RECT  20.473 7.992 21.42 8.16 ;
     RECT  20.473 8.16 21.408 8.184 ;
     RECT  20.473 8.184 21.42 8.304 ;
     RECT  20.473 8.304 21.408 8.328 ;
     RECT  20.473 8.328 21.42 8.496 ;
     RECT  20.473 8.496 21.408 8.52 ;
     RECT  20.473 8.52 21.42 8.64 ;
     RECT  20.473 8.64 21.408 8.664 ;
     RECT  20.473 8.664 21.42 8.832 ;
     RECT  20.473 8.832 21.408 8.856 ;
     RECT  20.473 8.856 21.42 8.976 ;
     RECT  20.473 8.976 21.408 9 ;
     RECT  20.473 9 21.42 9.168 ;
     RECT  20.473 9.168 21.408 9.192 ;
     RECT  20.473 9.192 21.42 9.36 ;
     RECT  20.473 9.36 21.408 9.384 ;
     RECT  20.473 9.384 21.42 9.504 ;
     RECT  20.473 9.504 21.408 9.528 ;
     RECT  20.473 9.528 21.42 9.696 ;
     RECT  20.473 9.696 21.408 9.72 ;
     RECT  20.473 9.72 21.42 9.84 ;
     RECT  20.473 9.84 21.408 9.864 ;
     RECT  20.473 9.864 21.42 10.032 ;
     RECT  20.473 10.032 21.408 10.056 ;
     RECT  20.473 10.056 21.42 10.176 ;
     RECT  20.473 10.176 21.408 10.2 ;
     RECT  20.473 10.2 21.42 10.368 ;
     RECT  20.473 10.368 21.408 10.392 ;
     RECT  20.473 10.392 21.42 10.56 ;
     RECT  20.473 10.56 21.408 10.584 ;
     RECT  20.473 10.584 21.42 10.704 ;
     RECT  20.473 10.704 21.408 10.728 ;
     RECT  20.473 10.728 21.42 10.896 ;
     RECT  20.473 10.896 21.408 10.92 ;
     RECT  20.473 10.92 21.42 11.04 ;
     RECT  20.473 11.04 21.408 11.064 ;
     RECT  20.473 11.064 21.42 11.232 ;
     RECT  20.473 11.232 21.408 11.256 ;
     RECT  20.473 11.256 21.42 11.376 ;
     RECT  20.473 11.376 21.408 11.4 ;
     RECT  20.473 11.4 21.42 11.568 ;
     RECT  20.473 11.568 21.408 11.592 ;
     RECT  20.473 11.592 21.42 11.76 ;
     RECT  20.473 11.76 21.408 11.784 ;
     RECT  20.473 11.784 21.42 11.904 ;
     RECT  20.473 11.904 21.408 11.928 ;
     RECT  20.473 11.928 21.42 12.096 ;
     RECT  20.473 12.096 21.408 12.12 ;
     RECT  20.473 12.12 21.42 12.24 ;
     RECT  20.473 12.24 21.408 12.264 ;
     RECT  20.473 12.264 21.42 12.432 ;
     RECT  20.473 12.432 21.408 12.456 ;
     RECT  20.473 12.456 21.42 12.624 ;
     RECT  20.473 12.624 21.408 12.648 ;
     RECT  20.473 12.648 21.42 12.768 ;
     RECT  20.473 12.768 21.408 12.792 ;
     RECT  20.473 12.792 21.42 13.152 ;
     RECT  20.473 13.152 21.408 13.176 ;
     RECT  20.473 13.176 21.42 13.344 ;
     RECT  20.473 13.344 21.408 13.368 ;
     RECT  20.473 13.368 21.42 13.536 ;
     RECT  20.473 13.536 21.408 13.56 ;
     RECT  20.473 13.56 21.42 13.68 ;
     RECT  20.473 13.68 21.408 13.704 ;
     RECT  20.473 13.704 21.42 13.872 ;
     RECT  20.473 13.872 21.408 13.896 ;
     RECT  20.473 13.896 21.42 14.016 ;
     RECT  20.473 14.016 21.408 14.04 ;
     RECT  20.473 14.04 21.42 14.208 ;
     RECT  20.473 14.208 21.408 14.232 ;
     RECT  20.473 14.232 21.42 14.352 ;
     RECT  20.473 14.352 21.408 14.376 ;
     RECT  20.473 14.376 21.42 14.544 ;
     RECT  20.473 14.544 21.408 14.568 ;
     RECT  20.473 14.568 21.42 14.736 ;
     RECT  20.473 14.736 21.408 14.76 ;
     RECT  20.473 14.76 21.42 14.88 ;
     RECT  20.473 14.88 21.408 14.904 ;
     RECT  20.473 14.904 21.42 15.072 ;
     RECT  20.473 15.072 21.408 15.096 ;
     RECT  20.473 15.096 21.42 15.216 ;
     RECT  20.473 15.216 21.408 15.24 ;
     RECT  20.473 15.24 21.42 15.408 ;
     RECT  20.473 15.408 21.408 15.432 ;
     RECT  20.473 15.432 21.42 15.552 ;
     RECT  20.473 15.552 21.408 15.576 ;
     RECT  20.473 15.576 21.42 15.744 ;
     RECT  20.473 15.744 21.408 15.768 ;
     RECT  20.473 15.768 21.42 15.936 ;
     RECT  20.473 15.936 21.408 15.96 ;
     RECT  20.473 15.96 21.42 16.08 ;
     RECT  20.473 16.08 21.408 16.104 ;
     RECT  20.473 16.104 21.42 16.272 ;
     RECT  20.473 16.272 21.408 16.296 ;
     RECT  20.473 16.296 21.42 16.416 ;
     RECT  20.473 16.416 21.408 16.44 ;
     RECT  20.473 16.44 21.42 16.608 ;
     RECT  20.473 16.608 21.408 16.632 ;
     RECT  20.473 16.632 21.42 16.8 ;
     RECT  20.473 16.8 21.408 16.824 ;
     RECT  20.473 16.824 21.42 16.944 ;
     RECT  20.473 16.944 21.408 16.968 ;
     RECT  20.473 16.968 21.42 17.136 ;
     RECT  20.473 17.136 21.408 17.16 ;
     RECT  20.473 17.16 21.42 17.28 ;
     RECT  20.473 17.28 21.408 17.304 ;
     RECT  20.473 17.304 21.42 17.472 ;
     RECT  20.473 17.472 21.408 17.496 ;
     RECT  20.473 17.496 21.42 17.616 ;
     RECT  20.473 17.616 21.408 17.64 ;
     RECT  20.473 17.64 21.42 17.808 ;
     RECT  20.473 17.808 21.408 17.832 ;
     RECT  20.473 17.832 21.42 18 ;
     RECT  20.473 18 21.408 18.024 ;
     RECT  20.473 18.024 21.42 18.144 ;
     RECT  20.473 18.144 21.408 18.168 ;
     RECT  20.473 18.168 21.42 18.336 ;
     RECT  20.473 18.336 21.408 18.36 ;
     RECT  20.473 18.36 21.42 18.48 ;
     RECT  20.473 18.48 21.408 18.504 ;
     RECT  20.473 18.504 21.42 18.672 ;
     RECT  20.473 18.672 21.408 18.696 ;
     RECT  20.473 18.696 21.42 18.816 ;
     RECT  20.473 18.816 21.408 18.84 ;
     RECT  20.473 18.84 21.42 19.008 ;
     RECT  20.473 19.008 21.408 19.032 ;
     RECT  20.473 19.032 21.42 19.2 ;
     RECT  20.473 19.2 21.408 19.224 ;
     RECT  20.473 19.224 21.42 19.344 ;
     RECT  20.473 19.344 21.408 19.368 ;
     RECT  20.473 19.368 21.42 19.536 ;
     RECT  20.473 19.536 21.408 19.56 ;
     RECT  20.473 19.56 21.42 19.68 ;
     RECT  20.473 19.68 21.408 19.704 ;
     RECT  20.473 19.704 21.42 19.872 ;
     RECT  20.473 19.872 21.408 19.896 ;
     RECT  20.473 19.896 21.42 20.016 ;
     RECT  20.473 20.016 21.408 20.04 ;
     RECT  20.473 20.04 21.42 20.208 ;
     RECT  20.473 20.208 21.408 20.232 ;
     RECT  20.473 20.232 21.42 20.4 ;
     RECT  20.473 20.4 21.408 20.424 ;
     RECT  20.473 20.424 21.42 20.544 ;
     RECT  20.473 20.544 21.408 20.568 ;
     RECT  20.473 20.568 21.42 20.736 ;
     RECT  20.473 20.736 21.408 20.76 ;
     RECT  20.473 20.76 21.42 20.88 ;
     RECT  20.473 20.88 21.408 20.904 ;
     RECT  20.473 20.904 21.42 21.072 ;
     RECT  20.473 21.072 21.408 21.096 ;
     RECT  20.473 21.096 21.42 21.264 ;
     RECT  20.473 21.264 21.408 21.288 ;
     RECT  20.473 21.288 21.42 21.408 ;
     RECT  20.473 21.408 21.408 21.432 ;
     RECT  20.473 21.432 21.42 21.792 ;
     RECT  20.473 21.792 21.408 21.816 ;
     RECT  20.473 21.816 21.42 21.984 ;
     RECT  20.473 21.984 21.408 22.008 ;
     RECT  20.473 22.008 21.42 22.176 ;
     RECT  20.473 22.176 21.408 22.2 ;
     RECT  20.473 22.2 21.42 22.32 ;
     RECT  20.473 22.32 21.408 22.344 ;
     RECT  20.473 22.344 21.42 22.512 ;
     RECT  20.473 22.512 21.408 22.536 ;
     RECT  20.473 22.536 21.42 22.656 ;
     RECT  20.473 22.656 21.408 22.68 ;
     RECT  20.473 22.68 21.42 22.848 ;
     RECT  20.473 22.848 21.408 22.872 ;
     RECT  20.473 22.872 21.42 22.992 ;
     RECT  20.473 22.992 21.408 23.016 ;
     RECT  20.473 23.016 21.42 23.184 ;
     RECT  20.473 23.184 21.408 23.208 ;
     RECT  20.473 23.208 21.42 23.376 ;
     RECT  20.473 23.376 21.408 23.4 ;
     RECT  20.473 23.4 21.42 23.52 ;
     RECT  20.473 23.52 21.408 23.544 ;
     RECT  20.473 23.544 21.42 23.712 ;
     RECT  20.473 23.712 21.408 23.736 ;
     RECT  20.473 23.736 21.42 23.856 ;
     RECT  20.473 23.856 21.408 23.88 ;
     RECT  20.473 23.88 21.42 24.048 ;
     RECT  20.473 24.048 21.408 24.072 ;
     RECT  20.473 24.072 21.42 24.192 ;
     RECT  20.473 24.192 21.408 24.216 ;
     RECT  20.473 24.216 21.42 24.384 ;
     RECT  20.473 24.384 21.408 24.408 ;
     RECT  20.473 24.408 21.42 24.576 ;
     RECT  20.473 24.576 21.408 24.6 ;
     RECT  20.473 24.6 21.42 24.72 ;
     RECT  20.473 24.72 21.408 24.744 ;
     RECT  20.473 24.744 21.42 24.912 ;
     RECT  20.473 24.912 21.408 24.936 ;
     RECT  20.473 24.936 21.42 25.056 ;
     RECT  20.473 25.056 21.408 25.08 ;
     RECT  20.473 25.08 21.42 25.248 ;
     RECT  20.473 25.248 21.408 25.272 ;
     RECT  20.473 25.272 21.42 25.44 ;
     RECT  20.473 25.44 21.408 25.464 ;
     RECT  20.473 25.464 21.42 25.584 ;
     RECT  20.473 25.584 21.408 25.608 ;
     RECT  20.473 25.608 21.42 25.776 ;
     RECT  20.473 25.776 21.408 25.8 ;
     RECT  20.473 25.8 21.42 25.92 ;
     RECT  20.473 25.92 21.408 25.944 ;
     RECT  20.473 25.944 21.42 26.112 ;
     RECT  20.473 26.112 21.408 26.136 ;
     RECT  20.473 26.136 21.42 26.256 ;
     RECT  20.473 26.256 21.408 26.28 ;
     RECT  20.473 26.28 21.42 26.448 ;
     RECT  20.473 26.448 21.408 26.472 ;
     RECT  20.473 26.472 21.42 26.64 ;
     RECT  20.473 26.64 21.408 26.664 ;
     RECT  20.473 26.664 21.42 26.784 ;
     RECT  20.473 26.784 21.408 26.808 ;
     RECT  20.473 26.808 21.42 26.976 ;
     RECT  20.473 26.976 21.408 27 ;
     RECT  20.473 27 21.42 27.12 ;
     RECT  20.473 27.12 21.408 27.144 ;
     RECT  20.473 27.144 21.42 27.312 ;
     RECT  20.473 27.312 21.408 27.336 ;
     RECT  20.473 27.336 21.42 27.456 ;
     RECT  20.473 27.456 21.408 27.48 ;
     RECT  20.473 27.48 21.42 27.648 ;
     RECT  20.473 27.648 21.408 27.672 ;
     RECT  20.473 27.672 21.42 27.84 ;
     RECT  20.473 27.84 21.408 27.864 ;
     RECT  20.473 27.864 21.42 27.984 ;
     RECT  20.473 27.984 21.408 28.008 ;
     RECT  20.473 28.008 21.42 28.176 ;
     RECT  20.473 28.176 21.408 28.2 ;
     RECT  20.473 28.2 21.42 28.32 ;
     RECT  20.473 28.32 21.408 28.344 ;
     RECT  20.473 28.344 21.42 28.512 ;
     RECT  20.473 28.512 21.408 28.536 ;
     RECT  20.473 28.536 21.42 28.656 ;
     RECT  20.473 28.656 21.408 28.68 ;
     RECT  20.473 28.68 21.42 28.848 ;
     RECT  20.473 28.848 21.408 28.872 ;
     RECT  20.473 28.872 21.42 29.04 ;
     RECT  20.473 29.04 21.408 29.064 ;
     RECT  20.473 29.064 21.42 29.184 ;
     RECT  20.473 29.184 21.408 29.208 ;
     RECT  20.473 29.208 21.42 29.376 ;
     RECT  20.473 29.376 21.408 29.4 ;
     RECT  20.473 29.4 21.42 29.52 ;
     RECT  20.473 29.52 21.408 29.544 ;
     RECT  20.473 29.544 21.42 29.712 ;
     RECT  20.473 29.712 21.408 29.736 ;
     RECT  20.473 29.736 21.42 29.904 ;
     RECT  20.473 29.904 21.408 29.928 ;
     RECT  20.473 29.928 21.42 30.048 ;
     RECT  20.473 30.048 21.408 30.072 ;
    LAYER M5 ;
     RECT  10.8 1.763 10.812 2.137 ;
     RECT  2.4 2.137 2.52 2.151 ;
     RECT  5.1 2.137 5.22 2.151 ;
     RECT  7.8 2.137 7.92 2.151 ;
     RECT  13.2 2.137 13.32 2.151 ;
     RECT  15.9 2.137 16.02 2.151 ;
     RECT  18.6 2.137 18.72 2.151 ;
     RECT  2.4 2.151 2.712 6.037 ;
     RECT  7.8 2.151 8.112 6.805 ;
     RECT  2.4 6.037 3.24 6.899 ;
     RECT  18.6 2.151 18.912 7.669 ;
     RECT  5.1 2.151 5.412 7.909 ;
     RECT  18.384 7.669 18.912 7.957 ;
     RECT  18.384 7.957 19.368 8.675 ;
     RECT  7.8 6.805 8.232 9.923 ;
     RECT  2.4 6.899 2.712 10.789 ;
     RECT  2.304 10.789 2.712 10.885 ;
     RECT  2.304 10.885 2.856 10.931 ;
     RECT  5.1 7.909 5.976 11.749 ;
     RECT  7.8 9.923 8.112 12.229 ;
     RECT  18.384 8.675 18.912 14.101 ;
     RECT  4.896 11.749 5.976 14.243 ;
     RECT  4.896 14.243 5.412 14.867 ;
     RECT  7.8 12.229 8.232 17.459 ;
     RECT  15.9 2.151 16.212 19.333 ;
     RECT  17.904 14.101 18.912 22.259 ;
     RECT  2.4 10.931 2.856 23.411 ;
     RECT  18.384 22.259 18.912 25.715 ;
     RECT  15.792 19.333 16.212 27.395 ;
     RECT  2.4 23.411 2.712 32.409 ;
     RECT  5.1 14.867 5.412 32.409 ;
     RECT  7.8 17.459 8.112 32.409 ;
     RECT  10.5 2.137 10.812 32.409 ;
     RECT  13.2 2.151 13.512 32.409 ;
     RECT  15.9 27.395 16.212 32.409 ;
     RECT  18.6 25.715 18.912 32.409 ;
     RECT  2.4 32.409 2.52 32.423 ;
     RECT  5.1 32.409 5.22 32.423 ;
     RECT  7.8 32.409 7.92 32.423 ;
     RECT  10.5 32.409 10.62 32.423 ;
     RECT  13.2 32.409 13.32 32.423 ;
     RECT  15.9 32.409 16.02 32.423 ;
     RECT  18.6 32.409 18.72 32.423 ;
  END
END hbfd_rly_48_WE_fc_f4
END LIBRARY
